VERSION 5.8 ;
BUSBITCHARS "[]" ;
DIVIDERCHAR "/" ;
UNITS
    DATABASE MICRONS 1000 ;
END UNITS

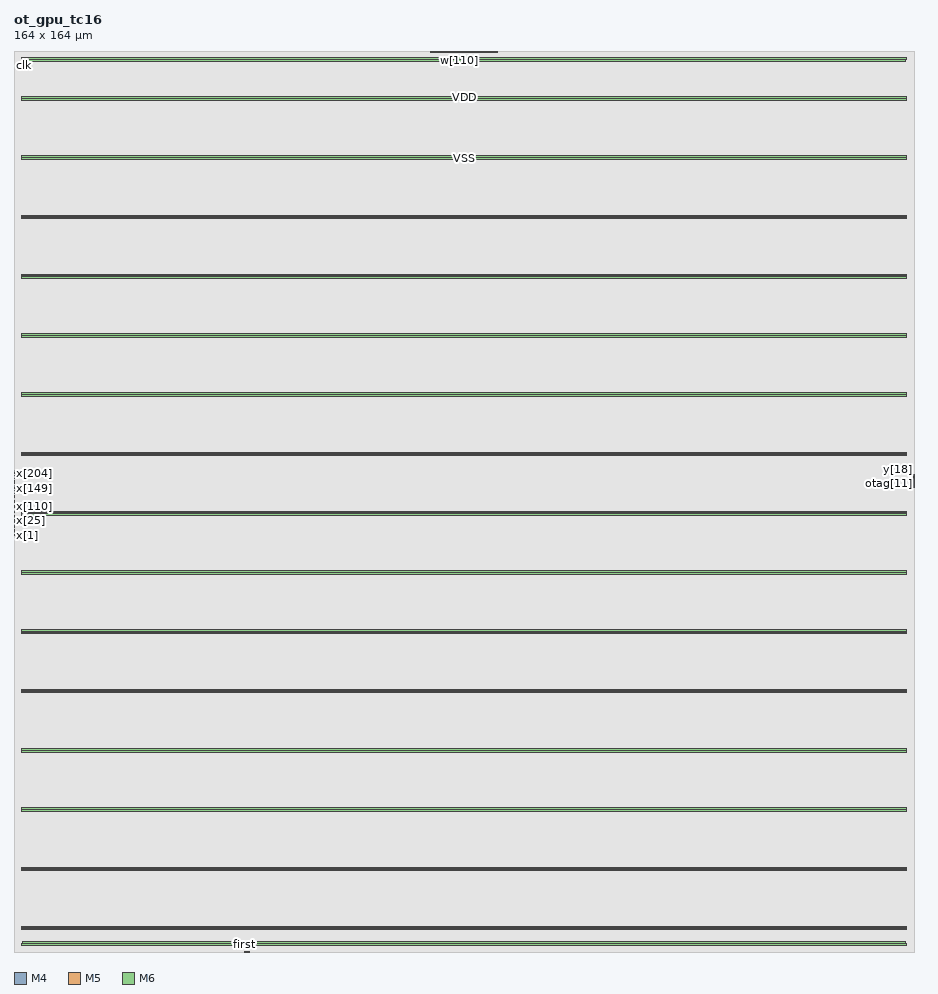
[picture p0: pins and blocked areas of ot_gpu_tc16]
MACRO ot_gpu_tc16
  FOREIGN ot_gpu_tc16 0 0 ;
  CLASS BLOCK ;
  SIZE 164 BY 164 ;
  PIN clk
    DIRECTION INPUT ;
    USE SIGNAL ;
    PORT
      LAYER M4 ;
        RECT  0 161.568 0.084 161.592 ;
    END
  END clk
  PIN fault
    DIRECTION OUTPUT ;
    USE SIGNAL ;
    PORT
      LAYER M4 ;
        RECT  163.916 84.72 164 84.744 ;
    END
  END fault
  PIN first
    DIRECTION INPUT ;
    USE SIGNAL ;
    PORT
      LAYER M5 ;
        RECT  42 0 42.024 0.084 ;
    END
  END first
  PIN last
    DIRECTION INPUT ;
    USE SIGNAL ;
    PORT
      LAYER M5 ;
        RECT  42.048 0 42.072 0.084 ;
    END
  END last
  PIN otag[0]
    DIRECTION OUTPUT ;
    USE SIGNAL ;
    PORT
      LAYER M4 ;
        RECT  163.916 84.768 164 84.792 ;
    END
  END otag[0]
  PIN otag[10]
    DIRECTION OUTPUT ;
    USE SIGNAL ;
    PORT
      LAYER M4 ;
        RECT  163.916 85.248 164 85.272 ;
    END
  END otag[10]
  PIN otag[11]
    DIRECTION OUTPUT ;
    USE SIGNAL ;
    PORT
      LAYER M4 ;
        RECT  163.916 85.296 164 85.32 ;
    END
  END otag[11]
  PIN otag[12]
    DIRECTION OUTPUT ;
    USE SIGNAL ;
    PORT
      LAYER M4 ;
        RECT  163.916 85.344 164 85.368 ;
    END
  END otag[12]
  PIN otag[13]
    DIRECTION OUTPUT ;
    USE SIGNAL ;
    PORT
      LAYER M4 ;
        RECT  163.916 85.392 164 85.416 ;
    END
  END otag[13]
  PIN otag[14]
    DIRECTION OUTPUT ;
    USE SIGNAL ;
    PORT
      LAYER M4 ;
        RECT  163.916 85.44 164 85.464 ;
    END
  END otag[14]
  PIN otag[15]
    DIRECTION OUTPUT ;
    USE SIGNAL ;
    PORT
      LAYER M4 ;
        RECT  163.916 85.488 164 85.512 ;
    END
  END otag[15]
  PIN otag[1]
    DIRECTION OUTPUT ;
    USE SIGNAL ;
    PORT
      LAYER M4 ;
        RECT  163.916 84.816 164 84.84 ;
    END
  END otag[1]
  PIN otag[2]
    DIRECTION OUTPUT ;
    USE SIGNAL ;
    PORT
      LAYER M4 ;
        RECT  163.916 84.864 164 84.888 ;
    END
  END otag[2]
  PIN otag[3]
    DIRECTION OUTPUT ;
    USE SIGNAL ;
    PORT
      LAYER M4 ;
        RECT  163.916 84.912 164 84.936 ;
    END
  END otag[3]
  PIN otag[4]
    DIRECTION OUTPUT ;
    USE SIGNAL ;
    PORT
      LAYER M4 ;
        RECT  163.916 84.96 164 84.984 ;
    END
  END otag[4]
  PIN otag[5]
    DIRECTION OUTPUT ;
    USE SIGNAL ;
    PORT
      LAYER M4 ;
        RECT  163.916 85.008 164 85.032 ;
    END
  END otag[5]
  PIN otag[6]
    DIRECTION OUTPUT ;
    USE SIGNAL ;
    PORT
      LAYER M4 ;
        RECT  163.916 85.056 164 85.08 ;
    END
  END otag[6]
  PIN otag[7]
    DIRECTION OUTPUT ;
    USE SIGNAL ;
    PORT
      LAYER M4 ;
        RECT  163.916 85.104 164 85.128 ;
    END
  END otag[7]
  PIN otag[8]
    DIRECTION OUTPUT ;
    USE SIGNAL ;
    PORT
      LAYER M4 ;
        RECT  163.916 85.152 164 85.176 ;
    END
  END otag[8]
  PIN otag[9]
    DIRECTION OUTPUT ;
    USE SIGNAL ;
    PORT
      LAYER M4 ;
        RECT  163.916 85.2 164 85.224 ;
    END
  END otag[9]
  PIN ov
    DIRECTION OUTPUT ;
    USE SIGNAL ;
    PORT
      LAYER M4 ;
        RECT  163.916 85.536 164 85.56 ;
    END
  END ov
  PIN rst_n
    DIRECTION INPUT ;
    USE SIGNAL ;
    PORT
      LAYER M5 ;
        RECT  42.096 0 42.12 0.084 ;
    END
  END rst_n
  PIN tag[0]
    DIRECTION INPUT ;
    USE SIGNAL ;
    PORT
      LAYER M5 ;
        RECT  42.144 0 42.168 0.084 ;
    END
  END tag[0]
  PIN tag[10]
    DIRECTION INPUT ;
    USE SIGNAL ;
    PORT
      LAYER M5 ;
        RECT  42.624 0 42.648 0.084 ;
    END
  END tag[10]
  PIN tag[11]
    DIRECTION INPUT ;
    USE SIGNAL ;
    PORT
      LAYER M5 ;
        RECT  42.672 0 42.696 0.084 ;
    END
  END tag[11]
  PIN tag[12]
    DIRECTION INPUT ;
    USE SIGNAL ;
    PORT
      LAYER M5 ;
        RECT  42.72 0 42.744 0.084 ;
    END
  END tag[12]
  PIN tag[13]
    DIRECTION INPUT ;
    USE SIGNAL ;
    PORT
      LAYER M5 ;
        RECT  42.768 0 42.792 0.084 ;
    END
  END tag[13]
  PIN tag[14]
    DIRECTION INPUT ;
    USE SIGNAL ;
    PORT
      LAYER M5 ;
        RECT  42.816 0 42.84 0.084 ;
    END
  END tag[14]
  PIN tag[15]
    DIRECTION INPUT ;
    USE SIGNAL ;
    PORT
      LAYER M5 ;
        RECT  42.864 0 42.888 0.084 ;
    END
  END tag[15]
  PIN tag[1]
    DIRECTION INPUT ;
    USE SIGNAL ;
    PORT
      LAYER M5 ;
        RECT  42.192 0 42.216 0.084 ;
    END
  END tag[1]
  PIN tag[2]
    DIRECTION INPUT ;
    USE SIGNAL ;
    PORT
      LAYER M5 ;
        RECT  42.24 0 42.264 0.084 ;
    END
  END tag[2]
  PIN tag[3]
    DIRECTION INPUT ;
    USE SIGNAL ;
    PORT
      LAYER M5 ;
        RECT  42.288 0 42.312 0.084 ;
    END
  END tag[3]
  PIN tag[4]
    DIRECTION INPUT ;
    USE SIGNAL ;
    PORT
      LAYER M5 ;
        RECT  42.336 0 42.36 0.084 ;
    END
  END tag[4]
  PIN tag[5]
    DIRECTION INPUT ;
    USE SIGNAL ;
    PORT
      LAYER M5 ;
        RECT  42.384 0 42.408 0.084 ;
    END
  END tag[5]
  PIN tag[6]
    DIRECTION INPUT ;
    USE SIGNAL ;
    PORT
      LAYER M5 ;
        RECT  42.432 0 42.456 0.084 ;
    END
  END tag[6]
  PIN tag[7]
    DIRECTION INPUT ;
    USE SIGNAL ;
    PORT
      LAYER M5 ;
        RECT  42.48 0 42.504 0.084 ;
    END
  END tag[7]
  PIN tag[8]
    DIRECTION INPUT ;
    USE SIGNAL ;
    PORT
      LAYER M5 ;
        RECT  42.528 0 42.552 0.084 ;
    END
  END tag[8]
  PIN tag[9]
    DIRECTION INPUT ;
    USE SIGNAL ;
    PORT
      LAYER M5 ;
        RECT  42.576 0 42.6 0.084 ;
    END
  END tag[9]
  PIN v
    DIRECTION INPUT ;
    USE SIGNAL ;
    PORT
      LAYER M5 ;
        RECT  42.912 0 42.936 0.084 ;
    END
  END v
  PIN w[0]
    DIRECTION INPUT ;
    USE SIGNAL ;
    PORT
      LAYER M5 ;
        RECT  75.888 163.916 75.912 164 ;
    END
  END w[0]
  PIN w[100]
    DIRECTION INPUT ;
    USE SIGNAL ;
    PORT
      LAYER M5 ;
        RECT  80.688 163.916 80.712 164 ;
    END
  END w[100]
  PIN w[101]
    DIRECTION INPUT ;
    USE SIGNAL ;
    PORT
      LAYER M5 ;
        RECT  80.736 163.916 80.76 164 ;
    END
  END w[101]
  PIN w[102]
    DIRECTION INPUT ;
    USE SIGNAL ;
    PORT
      LAYER M5 ;
        RECT  80.784 163.916 80.808 164 ;
    END
  END w[102]
  PIN w[103]
    DIRECTION INPUT ;
    USE SIGNAL ;
    PORT
      LAYER M5 ;
        RECT  80.832 163.916 80.856 164 ;
    END
  END w[103]
  PIN w[104]
    DIRECTION INPUT ;
    USE SIGNAL ;
    PORT
      LAYER M5 ;
        RECT  80.88 163.916 80.904 164 ;
    END
  END w[104]
  PIN w[105]
    DIRECTION INPUT ;
    USE SIGNAL ;
    PORT
      LAYER M5 ;
        RECT  80.928 163.916 80.952 164 ;
    END
  END w[105]
  PIN w[106]
    DIRECTION INPUT ;
    USE SIGNAL ;
    PORT
      LAYER M5 ;
        RECT  80.976 163.916 81 164 ;
    END
  END w[106]
  PIN w[107]
    DIRECTION INPUT ;
    USE SIGNAL ;
    PORT
      LAYER M5 ;
        RECT  81.024 163.916 81.048 164 ;
    END
  END w[107]
  PIN w[108]
    DIRECTION INPUT ;
    USE SIGNAL ;
    PORT
      LAYER M5 ;
        RECT  81.072 163.916 81.096 164 ;
    END
  END w[108]
  PIN w[109]
    DIRECTION INPUT ;
    USE SIGNAL ;
    PORT
      LAYER M5 ;
        RECT  81.12 163.916 81.144 164 ;
    END
  END w[109]
  PIN w[10]
    DIRECTION INPUT ;
    USE SIGNAL ;
    PORT
      LAYER M5 ;
        RECT  76.368 163.916 76.392 164 ;
    END
  END w[10]
  PIN w[110]
    DIRECTION INPUT ;
    USE SIGNAL ;
    PORT
      LAYER M5 ;
        RECT  81.168 163.916 81.192 164 ;
    END
  END w[110]
  PIN w[111]
    DIRECTION INPUT ;
    USE SIGNAL ;
    PORT
      LAYER M5 ;
        RECT  81.216 163.916 81.24 164 ;
    END
  END w[111]
  PIN w[112]
    DIRECTION INPUT ;
    USE SIGNAL ;
    PORT
      LAYER M5 ;
        RECT  81.264 163.916 81.288 164 ;
    END
  END w[112]
  PIN w[113]
    DIRECTION INPUT ;
    USE SIGNAL ;
    PORT
      LAYER M5 ;
        RECT  81.312 163.916 81.336 164 ;
    END
  END w[113]
  PIN w[114]
    DIRECTION INPUT ;
    USE SIGNAL ;
    PORT
      LAYER M5 ;
        RECT  81.36 163.916 81.384 164 ;
    END
  END w[114]
  PIN w[115]
    DIRECTION INPUT ;
    USE SIGNAL ;
    PORT
      LAYER M5 ;
        RECT  81.408 163.916 81.432 164 ;
    END
  END w[115]
  PIN w[116]
    DIRECTION INPUT ;
    USE SIGNAL ;
    PORT
      LAYER M5 ;
        RECT  81.456 163.916 81.48 164 ;
    END
  END w[116]
  PIN w[117]
    DIRECTION INPUT ;
    USE SIGNAL ;
    PORT
      LAYER M5 ;
        RECT  81.504 163.916 81.528 164 ;
    END
  END w[117]
  PIN w[118]
    DIRECTION INPUT ;
    USE SIGNAL ;
    PORT
      LAYER M5 ;
        RECT  81.552 163.916 81.576 164 ;
    END
  END w[118]
  PIN w[119]
    DIRECTION INPUT ;
    USE SIGNAL ;
    PORT
      LAYER M5 ;
        RECT  81.6 163.916 81.624 164 ;
    END
  END w[119]
  PIN w[11]
    DIRECTION INPUT ;
    USE SIGNAL ;
    PORT
      LAYER M5 ;
        RECT  76.416 163.916 76.44 164 ;
    END
  END w[11]
  PIN w[120]
    DIRECTION INPUT ;
    USE SIGNAL ;
    PORT
      LAYER M5 ;
        RECT  81.648 163.916 81.672 164 ;
    END
  END w[120]
  PIN w[121]
    DIRECTION INPUT ;
    USE SIGNAL ;
    PORT
      LAYER M5 ;
        RECT  81.696 163.916 81.72 164 ;
    END
  END w[121]
  PIN w[122]
    DIRECTION INPUT ;
    USE SIGNAL ;
    PORT
      LAYER M5 ;
        RECT  81.744 163.916 81.768 164 ;
    END
  END w[122]
  PIN w[123]
    DIRECTION INPUT ;
    USE SIGNAL ;
    PORT
      LAYER M5 ;
        RECT  81.792 163.916 81.816 164 ;
    END
  END w[123]
  PIN w[124]
    DIRECTION INPUT ;
    USE SIGNAL ;
    PORT
      LAYER M5 ;
        RECT  81.84 163.916 81.864 164 ;
    END
  END w[124]
  PIN w[125]
    DIRECTION INPUT ;
    USE SIGNAL ;
    PORT
      LAYER M5 ;
        RECT  81.888 163.916 81.912 164 ;
    END
  END w[125]
  PIN w[126]
    DIRECTION INPUT ;
    USE SIGNAL ;
    PORT
      LAYER M5 ;
        RECT  81.936 163.916 81.96 164 ;
    END
  END w[126]
  PIN w[127]
    DIRECTION INPUT ;
    USE SIGNAL ;
    PORT
      LAYER M5 ;
        RECT  81.984 163.916 82.008 164 ;
    END
  END w[127]
  PIN w[128]
    DIRECTION INPUT ;
    USE SIGNAL ;
    PORT
      LAYER M5 ;
        RECT  82.032 163.916 82.056 164 ;
    END
  END w[128]
  PIN w[129]
    DIRECTION INPUT ;
    USE SIGNAL ;
    PORT
      LAYER M5 ;
        RECT  82.08 163.916 82.104 164 ;
    END
  END w[129]
  PIN w[12]
    DIRECTION INPUT ;
    USE SIGNAL ;
    PORT
      LAYER M5 ;
        RECT  76.464 163.916 76.488 164 ;
    END
  END w[12]
  PIN w[130]
    DIRECTION INPUT ;
    USE SIGNAL ;
    PORT
      LAYER M5 ;
        RECT  82.128 163.916 82.152 164 ;
    END
  END w[130]
  PIN w[131]
    DIRECTION INPUT ;
    USE SIGNAL ;
    PORT
      LAYER M5 ;
        RECT  82.176 163.916 82.2 164 ;
    END
  END w[131]
  PIN w[132]
    DIRECTION INPUT ;
    USE SIGNAL ;
    PORT
      LAYER M5 ;
        RECT  82.224 163.916 82.248 164 ;
    END
  END w[132]
  PIN w[133]
    DIRECTION INPUT ;
    USE SIGNAL ;
    PORT
      LAYER M5 ;
        RECT  82.272 163.916 82.296 164 ;
    END
  END w[133]
  PIN w[134]
    DIRECTION INPUT ;
    USE SIGNAL ;
    PORT
      LAYER M5 ;
        RECT  82.32 163.916 82.344 164 ;
    END
  END w[134]
  PIN w[135]
    DIRECTION INPUT ;
    USE SIGNAL ;
    PORT
      LAYER M5 ;
        RECT  82.368 163.916 82.392 164 ;
    END
  END w[135]
  PIN w[136]
    DIRECTION INPUT ;
    USE SIGNAL ;
    PORT
      LAYER M5 ;
        RECT  82.416 163.916 82.44 164 ;
    END
  END w[136]
  PIN w[137]
    DIRECTION INPUT ;
    USE SIGNAL ;
    PORT
      LAYER M5 ;
        RECT  82.464 163.916 82.488 164 ;
    END
  END w[137]
  PIN w[138]
    DIRECTION INPUT ;
    USE SIGNAL ;
    PORT
      LAYER M5 ;
        RECT  82.512 163.916 82.536 164 ;
    END
  END w[138]
  PIN w[139]
    DIRECTION INPUT ;
    USE SIGNAL ;
    PORT
      LAYER M5 ;
        RECT  82.56 163.916 82.584 164 ;
    END
  END w[139]
  PIN w[13]
    DIRECTION INPUT ;
    USE SIGNAL ;
    PORT
      LAYER M5 ;
        RECT  76.512 163.916 76.536 164 ;
    END
  END w[13]
  PIN w[140]
    DIRECTION INPUT ;
    USE SIGNAL ;
    PORT
      LAYER M5 ;
        RECT  82.608 163.916 82.632 164 ;
    END
  END w[140]
  PIN w[141]
    DIRECTION INPUT ;
    USE SIGNAL ;
    PORT
      LAYER M5 ;
        RECT  82.656 163.916 82.68 164 ;
    END
  END w[141]
  PIN w[142]
    DIRECTION INPUT ;
    USE SIGNAL ;
    PORT
      LAYER M5 ;
        RECT  82.704 163.916 82.728 164 ;
    END
  END w[142]
  PIN w[143]
    DIRECTION INPUT ;
    USE SIGNAL ;
    PORT
      LAYER M5 ;
        RECT  82.752 163.916 82.776 164 ;
    END
  END w[143]
  PIN w[144]
    DIRECTION INPUT ;
    USE SIGNAL ;
    PORT
      LAYER M5 ;
        RECT  82.8 163.916 82.824 164 ;
    END
  END w[144]
  PIN w[145]
    DIRECTION INPUT ;
    USE SIGNAL ;
    PORT
      LAYER M5 ;
        RECT  82.848 163.916 82.872 164 ;
    END
  END w[145]
  PIN w[146]
    DIRECTION INPUT ;
    USE SIGNAL ;
    PORT
      LAYER M5 ;
        RECT  82.896 163.916 82.92 164 ;
    END
  END w[146]
  PIN w[147]
    DIRECTION INPUT ;
    USE SIGNAL ;
    PORT
      LAYER M5 ;
        RECT  82.944 163.916 82.968 164 ;
    END
  END w[147]
  PIN w[148]
    DIRECTION INPUT ;
    USE SIGNAL ;
    PORT
      LAYER M5 ;
        RECT  82.992 163.916 83.016 164 ;
    END
  END w[148]
  PIN w[149]
    DIRECTION INPUT ;
    USE SIGNAL ;
    PORT
      LAYER M5 ;
        RECT  83.04 163.916 83.064 164 ;
    END
  END w[149]
  PIN w[14]
    DIRECTION INPUT ;
    USE SIGNAL ;
    PORT
      LAYER M5 ;
        RECT  76.56 163.916 76.584 164 ;
    END
  END w[14]
  PIN w[150]
    DIRECTION INPUT ;
    USE SIGNAL ;
    PORT
      LAYER M5 ;
        RECT  83.088 163.916 83.112 164 ;
    END
  END w[150]
  PIN w[151]
    DIRECTION INPUT ;
    USE SIGNAL ;
    PORT
      LAYER M5 ;
        RECT  83.136 163.916 83.16 164 ;
    END
  END w[151]
  PIN w[152]
    DIRECTION INPUT ;
    USE SIGNAL ;
    PORT
      LAYER M5 ;
        RECT  83.184 163.916 83.208 164 ;
    END
  END w[152]
  PIN w[153]
    DIRECTION INPUT ;
    USE SIGNAL ;
    PORT
      LAYER M5 ;
        RECT  83.232 163.916 83.256 164 ;
    END
  END w[153]
  PIN w[154]
    DIRECTION INPUT ;
    USE SIGNAL ;
    PORT
      LAYER M5 ;
        RECT  83.28 163.916 83.304 164 ;
    END
  END w[154]
  PIN w[155]
    DIRECTION INPUT ;
    USE SIGNAL ;
    PORT
      LAYER M5 ;
        RECT  83.328 163.916 83.352 164 ;
    END
  END w[155]
  PIN w[156]
    DIRECTION INPUT ;
    USE SIGNAL ;
    PORT
      LAYER M5 ;
        RECT  83.376 163.916 83.4 164 ;
    END
  END w[156]
  PIN w[157]
    DIRECTION INPUT ;
    USE SIGNAL ;
    PORT
      LAYER M5 ;
        RECT  83.424 163.916 83.448 164 ;
    END
  END w[157]
  PIN w[158]
    DIRECTION INPUT ;
    USE SIGNAL ;
    PORT
      LAYER M5 ;
        RECT  83.472 163.916 83.496 164 ;
    END
  END w[158]
  PIN w[159]
    DIRECTION INPUT ;
    USE SIGNAL ;
    PORT
      LAYER M5 ;
        RECT  83.52 163.916 83.544 164 ;
    END
  END w[159]
  PIN w[15]
    DIRECTION INPUT ;
    USE SIGNAL ;
    PORT
      LAYER M5 ;
        RECT  76.608 163.916 76.632 164 ;
    END
  END w[15]
  PIN w[160]
    DIRECTION INPUT ;
    USE SIGNAL ;
    PORT
      LAYER M5 ;
        RECT  83.568 163.916 83.592 164 ;
    END
  END w[160]
  PIN w[161]
    DIRECTION INPUT ;
    USE SIGNAL ;
    PORT
      LAYER M5 ;
        RECT  83.616 163.916 83.64 164 ;
    END
  END w[161]
  PIN w[162]
    DIRECTION INPUT ;
    USE SIGNAL ;
    PORT
      LAYER M5 ;
        RECT  83.664 163.916 83.688 164 ;
    END
  END w[162]
  PIN w[163]
    DIRECTION INPUT ;
    USE SIGNAL ;
    PORT
      LAYER M5 ;
        RECT  83.712 163.916 83.736 164 ;
    END
  END w[163]
  PIN w[164]
    DIRECTION INPUT ;
    USE SIGNAL ;
    PORT
      LAYER M5 ;
        RECT  83.76 163.916 83.784 164 ;
    END
  END w[164]
  PIN w[165]
    DIRECTION INPUT ;
    USE SIGNAL ;
    PORT
      LAYER M5 ;
        RECT  83.808 163.916 83.832 164 ;
    END
  END w[165]
  PIN w[166]
    DIRECTION INPUT ;
    USE SIGNAL ;
    PORT
      LAYER M5 ;
        RECT  83.856 163.916 83.88 164 ;
    END
  END w[166]
  PIN w[167]
    DIRECTION INPUT ;
    USE SIGNAL ;
    PORT
      LAYER M5 ;
        RECT  83.904 163.916 83.928 164 ;
    END
  END w[167]
  PIN w[168]
    DIRECTION INPUT ;
    USE SIGNAL ;
    PORT
      LAYER M5 ;
        RECT  83.952 163.916 83.976 164 ;
    END
  END w[168]
  PIN w[169]
    DIRECTION INPUT ;
    USE SIGNAL ;
    PORT
      LAYER M5 ;
        RECT  84 163.916 84.024 164 ;
    END
  END w[169]
  PIN w[16]
    DIRECTION INPUT ;
    USE SIGNAL ;
    PORT
      LAYER M5 ;
        RECT  76.656 163.916 76.68 164 ;
    END
  END w[16]
  PIN w[170]
    DIRECTION INPUT ;
    USE SIGNAL ;
    PORT
      LAYER M5 ;
        RECT  84.048 163.916 84.072 164 ;
    END
  END w[170]
  PIN w[171]
    DIRECTION INPUT ;
    USE SIGNAL ;
    PORT
      LAYER M5 ;
        RECT  84.096 163.916 84.12 164 ;
    END
  END w[171]
  PIN w[172]
    DIRECTION INPUT ;
    USE SIGNAL ;
    PORT
      LAYER M5 ;
        RECT  84.144 163.916 84.168 164 ;
    END
  END w[172]
  PIN w[173]
    DIRECTION INPUT ;
    USE SIGNAL ;
    PORT
      LAYER M5 ;
        RECT  84.192 163.916 84.216 164 ;
    END
  END w[173]
  PIN w[174]
    DIRECTION INPUT ;
    USE SIGNAL ;
    PORT
      LAYER M5 ;
        RECT  84.24 163.916 84.264 164 ;
    END
  END w[174]
  PIN w[175]
    DIRECTION INPUT ;
    USE SIGNAL ;
    PORT
      LAYER M5 ;
        RECT  84.288 163.916 84.312 164 ;
    END
  END w[175]
  PIN w[176]
    DIRECTION INPUT ;
    USE SIGNAL ;
    PORT
      LAYER M5 ;
        RECT  84.336 163.916 84.36 164 ;
    END
  END w[176]
  PIN w[177]
    DIRECTION INPUT ;
    USE SIGNAL ;
    PORT
      LAYER M5 ;
        RECT  84.384 163.916 84.408 164 ;
    END
  END w[177]
  PIN w[178]
    DIRECTION INPUT ;
    USE SIGNAL ;
    PORT
      LAYER M5 ;
        RECT  84.432 163.916 84.456 164 ;
    END
  END w[178]
  PIN w[179]
    DIRECTION INPUT ;
    USE SIGNAL ;
    PORT
      LAYER M5 ;
        RECT  84.48 163.916 84.504 164 ;
    END
  END w[179]
  PIN w[17]
    DIRECTION INPUT ;
    USE SIGNAL ;
    PORT
      LAYER M5 ;
        RECT  76.704 163.916 76.728 164 ;
    END
  END w[17]
  PIN w[180]
    DIRECTION INPUT ;
    USE SIGNAL ;
    PORT
      LAYER M5 ;
        RECT  84.528 163.916 84.552 164 ;
    END
  END w[180]
  PIN w[181]
    DIRECTION INPUT ;
    USE SIGNAL ;
    PORT
      LAYER M5 ;
        RECT  84.576 163.916 84.6 164 ;
    END
  END w[181]
  PIN w[182]
    DIRECTION INPUT ;
    USE SIGNAL ;
    PORT
      LAYER M5 ;
        RECT  84.624 163.916 84.648 164 ;
    END
  END w[182]
  PIN w[183]
    DIRECTION INPUT ;
    USE SIGNAL ;
    PORT
      LAYER M5 ;
        RECT  84.672 163.916 84.696 164 ;
    END
  END w[183]
  PIN w[184]
    DIRECTION INPUT ;
    USE SIGNAL ;
    PORT
      LAYER M5 ;
        RECT  84.72 163.916 84.744 164 ;
    END
  END w[184]
  PIN w[185]
    DIRECTION INPUT ;
    USE SIGNAL ;
    PORT
      LAYER M5 ;
        RECT  84.768 163.916 84.792 164 ;
    END
  END w[185]
  PIN w[186]
    DIRECTION INPUT ;
    USE SIGNAL ;
    PORT
      LAYER M5 ;
        RECT  84.816 163.916 84.84 164 ;
    END
  END w[186]
  PIN w[187]
    DIRECTION INPUT ;
    USE SIGNAL ;
    PORT
      LAYER M5 ;
        RECT  84.864 163.916 84.888 164 ;
    END
  END w[187]
  PIN w[188]
    DIRECTION INPUT ;
    USE SIGNAL ;
    PORT
      LAYER M5 ;
        RECT  84.912 163.916 84.936 164 ;
    END
  END w[188]
  PIN w[189]
    DIRECTION INPUT ;
    USE SIGNAL ;
    PORT
      LAYER M5 ;
        RECT  84.96 163.916 84.984 164 ;
    END
  END w[189]
  PIN w[18]
    DIRECTION INPUT ;
    USE SIGNAL ;
    PORT
      LAYER M5 ;
        RECT  76.752 163.916 76.776 164 ;
    END
  END w[18]
  PIN w[190]
    DIRECTION INPUT ;
    USE SIGNAL ;
    PORT
      LAYER M5 ;
        RECT  85.008 163.916 85.032 164 ;
    END
  END w[190]
  PIN w[191]
    DIRECTION INPUT ;
    USE SIGNAL ;
    PORT
      LAYER M5 ;
        RECT  85.056 163.916 85.08 164 ;
    END
  END w[191]
  PIN w[192]
    DIRECTION INPUT ;
    USE SIGNAL ;
    PORT
      LAYER M5 ;
        RECT  85.104 163.916 85.128 164 ;
    END
  END w[192]
  PIN w[193]
    DIRECTION INPUT ;
    USE SIGNAL ;
    PORT
      LAYER M5 ;
        RECT  85.152 163.916 85.176 164 ;
    END
  END w[193]
  PIN w[194]
    DIRECTION INPUT ;
    USE SIGNAL ;
    PORT
      LAYER M5 ;
        RECT  85.2 163.916 85.224 164 ;
    END
  END w[194]
  PIN w[195]
    DIRECTION INPUT ;
    USE SIGNAL ;
    PORT
      LAYER M5 ;
        RECT  85.248 163.916 85.272 164 ;
    END
  END w[195]
  PIN w[196]
    DIRECTION INPUT ;
    USE SIGNAL ;
    PORT
      LAYER M5 ;
        RECT  85.296 163.916 85.32 164 ;
    END
  END w[196]
  PIN w[197]
    DIRECTION INPUT ;
    USE SIGNAL ;
    PORT
      LAYER M5 ;
        RECT  85.344 163.916 85.368 164 ;
    END
  END w[197]
  PIN w[198]
    DIRECTION INPUT ;
    USE SIGNAL ;
    PORT
      LAYER M5 ;
        RECT  85.392 163.916 85.416 164 ;
    END
  END w[198]
  PIN w[199]
    DIRECTION INPUT ;
    USE SIGNAL ;
    PORT
      LAYER M5 ;
        RECT  85.44 163.916 85.464 164 ;
    END
  END w[199]
  PIN w[19]
    DIRECTION INPUT ;
    USE SIGNAL ;
    PORT
      LAYER M5 ;
        RECT  76.8 163.916 76.824 164 ;
    END
  END w[19]
  PIN w[1]
    DIRECTION INPUT ;
    USE SIGNAL ;
    PORT
      LAYER M5 ;
        RECT  75.936 163.916 75.96 164 ;
    END
  END w[1]
  PIN w[200]
    DIRECTION INPUT ;
    USE SIGNAL ;
    PORT
      LAYER M5 ;
        RECT  85.488 163.916 85.512 164 ;
    END
  END w[200]
  PIN w[201]
    DIRECTION INPUT ;
    USE SIGNAL ;
    PORT
      LAYER M5 ;
        RECT  85.536 163.916 85.56 164 ;
    END
  END w[201]
  PIN w[202]
    DIRECTION INPUT ;
    USE SIGNAL ;
    PORT
      LAYER M5 ;
        RECT  85.584 163.916 85.608 164 ;
    END
  END w[202]
  PIN w[203]
    DIRECTION INPUT ;
    USE SIGNAL ;
    PORT
      LAYER M5 ;
        RECT  85.632 163.916 85.656 164 ;
    END
  END w[203]
  PIN w[204]
    DIRECTION INPUT ;
    USE SIGNAL ;
    PORT
      LAYER M5 ;
        RECT  85.68 163.916 85.704 164 ;
    END
  END w[204]
  PIN w[205]
    DIRECTION INPUT ;
    USE SIGNAL ;
    PORT
      LAYER M5 ;
        RECT  85.728 163.916 85.752 164 ;
    END
  END w[205]
  PIN w[206]
    DIRECTION INPUT ;
    USE SIGNAL ;
    PORT
      LAYER M5 ;
        RECT  85.776 163.916 85.8 164 ;
    END
  END w[206]
  PIN w[207]
    DIRECTION INPUT ;
    USE SIGNAL ;
    PORT
      LAYER M5 ;
        RECT  85.824 163.916 85.848 164 ;
    END
  END w[207]
  PIN w[208]
    DIRECTION INPUT ;
    USE SIGNAL ;
    PORT
      LAYER M5 ;
        RECT  85.872 163.916 85.896 164 ;
    END
  END w[208]
  PIN w[209]
    DIRECTION INPUT ;
    USE SIGNAL ;
    PORT
      LAYER M5 ;
        RECT  85.92 163.916 85.944 164 ;
    END
  END w[209]
  PIN w[20]
    DIRECTION INPUT ;
    USE SIGNAL ;
    PORT
      LAYER M5 ;
        RECT  76.848 163.916 76.872 164 ;
    END
  END w[20]
  PIN w[210]
    DIRECTION INPUT ;
    USE SIGNAL ;
    PORT
      LAYER M5 ;
        RECT  85.968 163.916 85.992 164 ;
    END
  END w[210]
  PIN w[211]
    DIRECTION INPUT ;
    USE SIGNAL ;
    PORT
      LAYER M5 ;
        RECT  86.016 163.916 86.04 164 ;
    END
  END w[211]
  PIN w[212]
    DIRECTION INPUT ;
    USE SIGNAL ;
    PORT
      LAYER M5 ;
        RECT  86.064 163.916 86.088 164 ;
    END
  END w[212]
  PIN w[213]
    DIRECTION INPUT ;
    USE SIGNAL ;
    PORT
      LAYER M5 ;
        RECT  86.112 163.916 86.136 164 ;
    END
  END w[213]
  PIN w[214]
    DIRECTION INPUT ;
    USE SIGNAL ;
    PORT
      LAYER M5 ;
        RECT  86.16 163.916 86.184 164 ;
    END
  END w[214]
  PIN w[215]
    DIRECTION INPUT ;
    USE SIGNAL ;
    PORT
      LAYER M5 ;
        RECT  86.208 163.916 86.232 164 ;
    END
  END w[215]
  PIN w[216]
    DIRECTION INPUT ;
    USE SIGNAL ;
    PORT
      LAYER M5 ;
        RECT  86.256 163.916 86.28 164 ;
    END
  END w[216]
  PIN w[217]
    DIRECTION INPUT ;
    USE SIGNAL ;
    PORT
      LAYER M5 ;
        RECT  86.304 163.916 86.328 164 ;
    END
  END w[217]
  PIN w[218]
    DIRECTION INPUT ;
    USE SIGNAL ;
    PORT
      LAYER M5 ;
        RECT  86.352 163.916 86.376 164 ;
    END
  END w[218]
  PIN w[219]
    DIRECTION INPUT ;
    USE SIGNAL ;
    PORT
      LAYER M5 ;
        RECT  86.4 163.916 86.424 164 ;
    END
  END w[219]
  PIN w[21]
    DIRECTION INPUT ;
    USE SIGNAL ;
    PORT
      LAYER M5 ;
        RECT  76.896 163.916 76.92 164 ;
    END
  END w[21]
  PIN w[220]
    DIRECTION INPUT ;
    USE SIGNAL ;
    PORT
      LAYER M5 ;
        RECT  86.448 163.916 86.472 164 ;
    END
  END w[220]
  PIN w[221]
    DIRECTION INPUT ;
    USE SIGNAL ;
    PORT
      LAYER M5 ;
        RECT  86.496 163.916 86.52 164 ;
    END
  END w[221]
  PIN w[222]
    DIRECTION INPUT ;
    USE SIGNAL ;
    PORT
      LAYER M5 ;
        RECT  86.544 163.916 86.568 164 ;
    END
  END w[222]
  PIN w[223]
    DIRECTION INPUT ;
    USE SIGNAL ;
    PORT
      LAYER M5 ;
        RECT  86.592 163.916 86.616 164 ;
    END
  END w[223]
  PIN w[224]
    DIRECTION INPUT ;
    USE SIGNAL ;
    PORT
      LAYER M5 ;
        RECT  86.64 163.916 86.664 164 ;
    END
  END w[224]
  PIN w[225]
    DIRECTION INPUT ;
    USE SIGNAL ;
    PORT
      LAYER M5 ;
        RECT  86.688 163.916 86.712 164 ;
    END
  END w[225]
  PIN w[226]
    DIRECTION INPUT ;
    USE SIGNAL ;
    PORT
      LAYER M5 ;
        RECT  86.736 163.916 86.76 164 ;
    END
  END w[226]
  PIN w[227]
    DIRECTION INPUT ;
    USE SIGNAL ;
    PORT
      LAYER M5 ;
        RECT  86.784 163.916 86.808 164 ;
    END
  END w[227]
  PIN w[228]
    DIRECTION INPUT ;
    USE SIGNAL ;
    PORT
      LAYER M5 ;
        RECT  86.832 163.916 86.856 164 ;
    END
  END w[228]
  PIN w[229]
    DIRECTION INPUT ;
    USE SIGNAL ;
    PORT
      LAYER M5 ;
        RECT  86.88 163.916 86.904 164 ;
    END
  END w[229]
  PIN w[22]
    DIRECTION INPUT ;
    USE SIGNAL ;
    PORT
      LAYER M5 ;
        RECT  76.944 163.916 76.968 164 ;
    END
  END w[22]
  PIN w[230]
    DIRECTION INPUT ;
    USE SIGNAL ;
    PORT
      LAYER M5 ;
        RECT  86.928 163.916 86.952 164 ;
    END
  END w[230]
  PIN w[231]
    DIRECTION INPUT ;
    USE SIGNAL ;
    PORT
      LAYER M5 ;
        RECT  86.976 163.916 87 164 ;
    END
  END w[231]
  PIN w[232]
    DIRECTION INPUT ;
    USE SIGNAL ;
    PORT
      LAYER M5 ;
        RECT  87.024 163.916 87.048 164 ;
    END
  END w[232]
  PIN w[233]
    DIRECTION INPUT ;
    USE SIGNAL ;
    PORT
      LAYER M5 ;
        RECT  87.072 163.916 87.096 164 ;
    END
  END w[233]
  PIN w[234]
    DIRECTION INPUT ;
    USE SIGNAL ;
    PORT
      LAYER M5 ;
        RECT  87.12 163.916 87.144 164 ;
    END
  END w[234]
  PIN w[235]
    DIRECTION INPUT ;
    USE SIGNAL ;
    PORT
      LAYER M5 ;
        RECT  87.168 163.916 87.192 164 ;
    END
  END w[235]
  PIN w[236]
    DIRECTION INPUT ;
    USE SIGNAL ;
    PORT
      LAYER M5 ;
        RECT  87.216 163.916 87.24 164 ;
    END
  END w[236]
  PIN w[237]
    DIRECTION INPUT ;
    USE SIGNAL ;
    PORT
      LAYER M5 ;
        RECT  87.264 163.916 87.288 164 ;
    END
  END w[237]
  PIN w[238]
    DIRECTION INPUT ;
    USE SIGNAL ;
    PORT
      LAYER M5 ;
        RECT  87.312 163.916 87.336 164 ;
    END
  END w[238]
  PIN w[239]
    DIRECTION INPUT ;
    USE SIGNAL ;
    PORT
      LAYER M5 ;
        RECT  87.36 163.916 87.384 164 ;
    END
  END w[239]
  PIN w[23]
    DIRECTION INPUT ;
    USE SIGNAL ;
    PORT
      LAYER M5 ;
        RECT  76.992 163.916 77.016 164 ;
    END
  END w[23]
  PIN w[240]
    DIRECTION INPUT ;
    USE SIGNAL ;
    PORT
      LAYER M5 ;
        RECT  87.408 163.916 87.432 164 ;
    END
  END w[240]
  PIN w[241]
    DIRECTION INPUT ;
    USE SIGNAL ;
    PORT
      LAYER M5 ;
        RECT  87.456 163.916 87.48 164 ;
    END
  END w[241]
  PIN w[242]
    DIRECTION INPUT ;
    USE SIGNAL ;
    PORT
      LAYER M5 ;
        RECT  87.504 163.916 87.528 164 ;
    END
  END w[242]
  PIN w[243]
    DIRECTION INPUT ;
    USE SIGNAL ;
    PORT
      LAYER M5 ;
        RECT  87.552 163.916 87.576 164 ;
    END
  END w[243]
  PIN w[244]
    DIRECTION INPUT ;
    USE SIGNAL ;
    PORT
      LAYER M5 ;
        RECT  87.6 163.916 87.624 164 ;
    END
  END w[244]
  PIN w[245]
    DIRECTION INPUT ;
    USE SIGNAL ;
    PORT
      LAYER M5 ;
        RECT  87.648 163.916 87.672 164 ;
    END
  END w[245]
  PIN w[246]
    DIRECTION INPUT ;
    USE SIGNAL ;
    PORT
      LAYER M5 ;
        RECT  87.696 163.916 87.72 164 ;
    END
  END w[246]
  PIN w[247]
    DIRECTION INPUT ;
    USE SIGNAL ;
    PORT
      LAYER M5 ;
        RECT  87.744 163.916 87.768 164 ;
    END
  END w[247]
  PIN w[248]
    DIRECTION INPUT ;
    USE SIGNAL ;
    PORT
      LAYER M5 ;
        RECT  87.792 163.916 87.816 164 ;
    END
  END w[248]
  PIN w[249]
    DIRECTION INPUT ;
    USE SIGNAL ;
    PORT
      LAYER M5 ;
        RECT  87.84 163.916 87.864 164 ;
    END
  END w[249]
  PIN w[24]
    DIRECTION INPUT ;
    USE SIGNAL ;
    PORT
      LAYER M5 ;
        RECT  77.04 163.916 77.064 164 ;
    END
  END w[24]
  PIN w[250]
    DIRECTION INPUT ;
    USE SIGNAL ;
    PORT
      LAYER M5 ;
        RECT  87.888 163.916 87.912 164 ;
    END
  END w[250]
  PIN w[251]
    DIRECTION INPUT ;
    USE SIGNAL ;
    PORT
      LAYER M5 ;
        RECT  87.936 163.916 87.96 164 ;
    END
  END w[251]
  PIN w[252]
    DIRECTION INPUT ;
    USE SIGNAL ;
    PORT
      LAYER M5 ;
        RECT  87.984 163.916 88.008 164 ;
    END
  END w[252]
  PIN w[253]
    DIRECTION INPUT ;
    USE SIGNAL ;
    PORT
      LAYER M5 ;
        RECT  88.032 163.916 88.056 164 ;
    END
  END w[253]
  PIN w[254]
    DIRECTION INPUT ;
    USE SIGNAL ;
    PORT
      LAYER M5 ;
        RECT  88.08 163.916 88.104 164 ;
    END
  END w[254]
  PIN w[255]
    DIRECTION INPUT ;
    USE SIGNAL ;
    PORT
      LAYER M5 ;
        RECT  88.128 163.916 88.152 164 ;
    END
  END w[255]
  PIN w[25]
    DIRECTION INPUT ;
    USE SIGNAL ;
    PORT
      LAYER M5 ;
        RECT  77.088 163.916 77.112 164 ;
    END
  END w[25]
  PIN w[26]
    DIRECTION INPUT ;
    USE SIGNAL ;
    PORT
      LAYER M5 ;
        RECT  77.136 163.916 77.16 164 ;
    END
  END w[26]
  PIN w[27]
    DIRECTION INPUT ;
    USE SIGNAL ;
    PORT
      LAYER M5 ;
        RECT  77.184 163.916 77.208 164 ;
    END
  END w[27]
  PIN w[28]
    DIRECTION INPUT ;
    USE SIGNAL ;
    PORT
      LAYER M5 ;
        RECT  77.232 163.916 77.256 164 ;
    END
  END w[28]
  PIN w[29]
    DIRECTION INPUT ;
    USE SIGNAL ;
    PORT
      LAYER M5 ;
        RECT  77.28 163.916 77.304 164 ;
    END
  END w[29]
  PIN w[2]
    DIRECTION INPUT ;
    USE SIGNAL ;
    PORT
      LAYER M5 ;
        RECT  75.984 163.916 76.008 164 ;
    END
  END w[2]
  PIN w[30]
    DIRECTION INPUT ;
    USE SIGNAL ;
    PORT
      LAYER M5 ;
        RECT  77.328 163.916 77.352 164 ;
    END
  END w[30]
  PIN w[31]
    DIRECTION INPUT ;
    USE SIGNAL ;
    PORT
      LAYER M5 ;
        RECT  77.376 163.916 77.4 164 ;
    END
  END w[31]
  PIN w[32]
    DIRECTION INPUT ;
    USE SIGNAL ;
    PORT
      LAYER M5 ;
        RECT  77.424 163.916 77.448 164 ;
    END
  END w[32]
  PIN w[33]
    DIRECTION INPUT ;
    USE SIGNAL ;
    PORT
      LAYER M5 ;
        RECT  77.472 163.916 77.496 164 ;
    END
  END w[33]
  PIN w[34]
    DIRECTION INPUT ;
    USE SIGNAL ;
    PORT
      LAYER M5 ;
        RECT  77.52 163.916 77.544 164 ;
    END
  END w[34]
  PIN w[35]
    DIRECTION INPUT ;
    USE SIGNAL ;
    PORT
      LAYER M5 ;
        RECT  77.568 163.916 77.592 164 ;
    END
  END w[35]
  PIN w[36]
    DIRECTION INPUT ;
    USE SIGNAL ;
    PORT
      LAYER M5 ;
        RECT  77.616 163.916 77.64 164 ;
    END
  END w[36]
  PIN w[37]
    DIRECTION INPUT ;
    USE SIGNAL ;
    PORT
      LAYER M5 ;
        RECT  77.664 163.916 77.688 164 ;
    END
  END w[37]
  PIN w[38]
    DIRECTION INPUT ;
    USE SIGNAL ;
    PORT
      LAYER M5 ;
        RECT  77.712 163.916 77.736 164 ;
    END
  END w[38]
  PIN w[39]
    DIRECTION INPUT ;
    USE SIGNAL ;
    PORT
      LAYER M5 ;
        RECT  77.76 163.916 77.784 164 ;
    END
  END w[39]
  PIN w[3]
    DIRECTION INPUT ;
    USE SIGNAL ;
    PORT
      LAYER M5 ;
        RECT  76.032 163.916 76.056 164 ;
    END
  END w[3]
  PIN w[40]
    DIRECTION INPUT ;
    USE SIGNAL ;
    PORT
      LAYER M5 ;
        RECT  77.808 163.916 77.832 164 ;
    END
  END w[40]
  PIN w[41]
    DIRECTION INPUT ;
    USE SIGNAL ;
    PORT
      LAYER M5 ;
        RECT  77.856 163.916 77.88 164 ;
    END
  END w[41]
  PIN w[42]
    DIRECTION INPUT ;
    USE SIGNAL ;
    PORT
      LAYER M5 ;
        RECT  77.904 163.916 77.928 164 ;
    END
  END w[42]
  PIN w[43]
    DIRECTION INPUT ;
    USE SIGNAL ;
    PORT
      LAYER M5 ;
        RECT  77.952 163.916 77.976 164 ;
    END
  END w[43]
  PIN w[44]
    DIRECTION INPUT ;
    USE SIGNAL ;
    PORT
      LAYER M5 ;
        RECT  78 163.916 78.024 164 ;
    END
  END w[44]
  PIN w[45]
    DIRECTION INPUT ;
    USE SIGNAL ;
    PORT
      LAYER M5 ;
        RECT  78.048 163.916 78.072 164 ;
    END
  END w[45]
  PIN w[46]
    DIRECTION INPUT ;
    USE SIGNAL ;
    PORT
      LAYER M5 ;
        RECT  78.096 163.916 78.12 164 ;
    END
  END w[46]
  PIN w[47]
    DIRECTION INPUT ;
    USE SIGNAL ;
    PORT
      LAYER M5 ;
        RECT  78.144 163.916 78.168 164 ;
    END
  END w[47]
  PIN w[48]
    DIRECTION INPUT ;
    USE SIGNAL ;
    PORT
      LAYER M5 ;
        RECT  78.192 163.916 78.216 164 ;
    END
  END w[48]
  PIN w[49]
    DIRECTION INPUT ;
    USE SIGNAL ;
    PORT
      LAYER M5 ;
        RECT  78.24 163.916 78.264 164 ;
    END
  END w[49]
  PIN w[4]
    DIRECTION INPUT ;
    USE SIGNAL ;
    PORT
      LAYER M5 ;
        RECT  76.08 163.916 76.104 164 ;
    END
  END w[4]
  PIN w[50]
    DIRECTION INPUT ;
    USE SIGNAL ;
    PORT
      LAYER M5 ;
        RECT  78.288 163.916 78.312 164 ;
    END
  END w[50]
  PIN w[51]
    DIRECTION INPUT ;
    USE SIGNAL ;
    PORT
      LAYER M5 ;
        RECT  78.336 163.916 78.36 164 ;
    END
  END w[51]
  PIN w[52]
    DIRECTION INPUT ;
    USE SIGNAL ;
    PORT
      LAYER M5 ;
        RECT  78.384 163.916 78.408 164 ;
    END
  END w[52]
  PIN w[53]
    DIRECTION INPUT ;
    USE SIGNAL ;
    PORT
      LAYER M5 ;
        RECT  78.432 163.916 78.456 164 ;
    END
  END w[53]
  PIN w[54]
    DIRECTION INPUT ;
    USE SIGNAL ;
    PORT
      LAYER M5 ;
        RECT  78.48 163.916 78.504 164 ;
    END
  END w[54]
  PIN w[55]
    DIRECTION INPUT ;
    USE SIGNAL ;
    PORT
      LAYER M5 ;
        RECT  78.528 163.916 78.552 164 ;
    END
  END w[55]
  PIN w[56]
    DIRECTION INPUT ;
    USE SIGNAL ;
    PORT
      LAYER M5 ;
        RECT  78.576 163.916 78.6 164 ;
    END
  END w[56]
  PIN w[57]
    DIRECTION INPUT ;
    USE SIGNAL ;
    PORT
      LAYER M5 ;
        RECT  78.624 163.916 78.648 164 ;
    END
  END w[57]
  PIN w[58]
    DIRECTION INPUT ;
    USE SIGNAL ;
    PORT
      LAYER M5 ;
        RECT  78.672 163.916 78.696 164 ;
    END
  END w[58]
  PIN w[59]
    DIRECTION INPUT ;
    USE SIGNAL ;
    PORT
      LAYER M5 ;
        RECT  78.72 163.916 78.744 164 ;
    END
  END w[59]
  PIN w[5]
    DIRECTION INPUT ;
    USE SIGNAL ;
    PORT
      LAYER M5 ;
        RECT  76.128 163.916 76.152 164 ;
    END
  END w[5]
  PIN w[60]
    DIRECTION INPUT ;
    USE SIGNAL ;
    PORT
      LAYER M5 ;
        RECT  78.768 163.916 78.792 164 ;
    END
  END w[60]
  PIN w[61]
    DIRECTION INPUT ;
    USE SIGNAL ;
    PORT
      LAYER M5 ;
        RECT  78.816 163.916 78.84 164 ;
    END
  END w[61]
  PIN w[62]
    DIRECTION INPUT ;
    USE SIGNAL ;
    PORT
      LAYER M5 ;
        RECT  78.864 163.916 78.888 164 ;
    END
  END w[62]
  PIN w[63]
    DIRECTION INPUT ;
    USE SIGNAL ;
    PORT
      LAYER M5 ;
        RECT  78.912 163.916 78.936 164 ;
    END
  END w[63]
  PIN w[64]
    DIRECTION INPUT ;
    USE SIGNAL ;
    PORT
      LAYER M5 ;
        RECT  78.96 163.916 78.984 164 ;
    END
  END w[64]
  PIN w[65]
    DIRECTION INPUT ;
    USE SIGNAL ;
    PORT
      LAYER M5 ;
        RECT  79.008 163.916 79.032 164 ;
    END
  END w[65]
  PIN w[66]
    DIRECTION INPUT ;
    USE SIGNAL ;
    PORT
      LAYER M5 ;
        RECT  79.056 163.916 79.08 164 ;
    END
  END w[66]
  PIN w[67]
    DIRECTION INPUT ;
    USE SIGNAL ;
    PORT
      LAYER M5 ;
        RECT  79.104 163.916 79.128 164 ;
    END
  END w[67]
  PIN w[68]
    DIRECTION INPUT ;
    USE SIGNAL ;
    PORT
      LAYER M5 ;
        RECT  79.152 163.916 79.176 164 ;
    END
  END w[68]
  PIN w[69]
    DIRECTION INPUT ;
    USE SIGNAL ;
    PORT
      LAYER M5 ;
        RECT  79.2 163.916 79.224 164 ;
    END
  END w[69]
  PIN w[6]
    DIRECTION INPUT ;
    USE SIGNAL ;
    PORT
      LAYER M5 ;
        RECT  76.176 163.916 76.2 164 ;
    END
  END w[6]
  PIN w[70]
    DIRECTION INPUT ;
    USE SIGNAL ;
    PORT
      LAYER M5 ;
        RECT  79.248 163.916 79.272 164 ;
    END
  END w[70]
  PIN w[71]
    DIRECTION INPUT ;
    USE SIGNAL ;
    PORT
      LAYER M5 ;
        RECT  79.296 163.916 79.32 164 ;
    END
  END w[71]
  PIN w[72]
    DIRECTION INPUT ;
    USE SIGNAL ;
    PORT
      LAYER M5 ;
        RECT  79.344 163.916 79.368 164 ;
    END
  END w[72]
  PIN w[73]
    DIRECTION INPUT ;
    USE SIGNAL ;
    PORT
      LAYER M5 ;
        RECT  79.392 163.916 79.416 164 ;
    END
  END w[73]
  PIN w[74]
    DIRECTION INPUT ;
    USE SIGNAL ;
    PORT
      LAYER M5 ;
        RECT  79.44 163.916 79.464 164 ;
    END
  END w[74]
  PIN w[75]
    DIRECTION INPUT ;
    USE SIGNAL ;
    PORT
      LAYER M5 ;
        RECT  79.488 163.916 79.512 164 ;
    END
  END w[75]
  PIN w[76]
    DIRECTION INPUT ;
    USE SIGNAL ;
    PORT
      LAYER M5 ;
        RECT  79.536 163.916 79.56 164 ;
    END
  END w[76]
  PIN w[77]
    DIRECTION INPUT ;
    USE SIGNAL ;
    PORT
      LAYER M5 ;
        RECT  79.584 163.916 79.608 164 ;
    END
  END w[77]
  PIN w[78]
    DIRECTION INPUT ;
    USE SIGNAL ;
    PORT
      LAYER M5 ;
        RECT  79.632 163.916 79.656 164 ;
    END
  END w[78]
  PIN w[79]
    DIRECTION INPUT ;
    USE SIGNAL ;
    PORT
      LAYER M5 ;
        RECT  79.68 163.916 79.704 164 ;
    END
  END w[79]
  PIN w[7]
    DIRECTION INPUT ;
    USE SIGNAL ;
    PORT
      LAYER M5 ;
        RECT  76.224 163.916 76.248 164 ;
    END
  END w[7]
  PIN w[80]
    DIRECTION INPUT ;
    USE SIGNAL ;
    PORT
      LAYER M5 ;
        RECT  79.728 163.916 79.752 164 ;
    END
  END w[80]
  PIN w[81]
    DIRECTION INPUT ;
    USE SIGNAL ;
    PORT
      LAYER M5 ;
        RECT  79.776 163.916 79.8 164 ;
    END
  END w[81]
  PIN w[82]
    DIRECTION INPUT ;
    USE SIGNAL ;
    PORT
      LAYER M5 ;
        RECT  79.824 163.916 79.848 164 ;
    END
  END w[82]
  PIN w[83]
    DIRECTION INPUT ;
    USE SIGNAL ;
    PORT
      LAYER M5 ;
        RECT  79.872 163.916 79.896 164 ;
    END
  END w[83]
  PIN w[84]
    DIRECTION INPUT ;
    USE SIGNAL ;
    PORT
      LAYER M5 ;
        RECT  79.92 163.916 79.944 164 ;
    END
  END w[84]
  PIN w[85]
    DIRECTION INPUT ;
    USE SIGNAL ;
    PORT
      LAYER M5 ;
        RECT  79.968 163.916 79.992 164 ;
    END
  END w[85]
  PIN w[86]
    DIRECTION INPUT ;
    USE SIGNAL ;
    PORT
      LAYER M5 ;
        RECT  80.016 163.916 80.04 164 ;
    END
  END w[86]
  PIN w[87]
    DIRECTION INPUT ;
    USE SIGNAL ;
    PORT
      LAYER M5 ;
        RECT  80.064 163.916 80.088 164 ;
    END
  END w[87]
  PIN w[88]
    DIRECTION INPUT ;
    USE SIGNAL ;
    PORT
      LAYER M5 ;
        RECT  80.112 163.916 80.136 164 ;
    END
  END w[88]
  PIN w[89]
    DIRECTION INPUT ;
    USE SIGNAL ;
    PORT
      LAYER M5 ;
        RECT  80.16 163.916 80.184 164 ;
    END
  END w[89]
  PIN w[8]
    DIRECTION INPUT ;
    USE SIGNAL ;
    PORT
      LAYER M5 ;
        RECT  76.272 163.916 76.296 164 ;
    END
  END w[8]
  PIN w[90]
    DIRECTION INPUT ;
    USE SIGNAL ;
    PORT
      LAYER M5 ;
        RECT  80.208 163.916 80.232 164 ;
    END
  END w[90]
  PIN w[91]
    DIRECTION INPUT ;
    USE SIGNAL ;
    PORT
      LAYER M5 ;
        RECT  80.256 163.916 80.28 164 ;
    END
  END w[91]
  PIN w[92]
    DIRECTION INPUT ;
    USE SIGNAL ;
    PORT
      LAYER M5 ;
        RECT  80.304 163.916 80.328 164 ;
    END
  END w[92]
  PIN w[93]
    DIRECTION INPUT ;
    USE SIGNAL ;
    PORT
      LAYER M5 ;
        RECT  80.352 163.916 80.376 164 ;
    END
  END w[93]
  PIN w[94]
    DIRECTION INPUT ;
    USE SIGNAL ;
    PORT
      LAYER M5 ;
        RECT  80.4 163.916 80.424 164 ;
    END
  END w[94]
  PIN w[95]
    DIRECTION INPUT ;
    USE SIGNAL ;
    PORT
      LAYER M5 ;
        RECT  80.448 163.916 80.472 164 ;
    END
  END w[95]
  PIN w[96]
    DIRECTION INPUT ;
    USE SIGNAL ;
    PORT
      LAYER M5 ;
        RECT  80.496 163.916 80.52 164 ;
    END
  END w[96]
  PIN w[97]
    DIRECTION INPUT ;
    USE SIGNAL ;
    PORT
      LAYER M5 ;
        RECT  80.544 163.916 80.568 164 ;
    END
  END w[97]
  PIN w[98]
    DIRECTION INPUT ;
    USE SIGNAL ;
    PORT
      LAYER M5 ;
        RECT  80.592 163.916 80.616 164 ;
    END
  END w[98]
  PIN w[99]
    DIRECTION INPUT ;
    USE SIGNAL ;
    PORT
      LAYER M5 ;
        RECT  80.64 163.916 80.664 164 ;
    END
  END w[99]
  PIN w[9]
    DIRECTION INPUT ;
    USE SIGNAL ;
    PORT
      LAYER M5 ;
        RECT  76.32 163.916 76.344 164 ;
    END
  END w[9]
  PIN x[0]
    DIRECTION INPUT ;
    USE SIGNAL ;
    PORT
      LAYER M4 ;
        RECT  0 75.888 0.084 75.912 ;
    END
  END x[0]
  PIN x[100]
    DIRECTION INPUT ;
    USE SIGNAL ;
    PORT
      LAYER M4 ;
        RECT  0 80.688 0.084 80.712 ;
    END
  END x[100]
  PIN x[101]
    DIRECTION INPUT ;
    USE SIGNAL ;
    PORT
      LAYER M4 ;
        RECT  0 80.736 0.084 80.76 ;
    END
  END x[101]
  PIN x[102]
    DIRECTION INPUT ;
    USE SIGNAL ;
    PORT
      LAYER M4 ;
        RECT  0 80.784 0.084 80.808 ;
    END
  END x[102]
  PIN x[103]
    DIRECTION INPUT ;
    USE SIGNAL ;
    PORT
      LAYER M4 ;
        RECT  0 80.832 0.084 80.856 ;
    END
  END x[103]
  PIN x[104]
    DIRECTION INPUT ;
    USE SIGNAL ;
    PORT
      LAYER M4 ;
        RECT  0 80.88 0.084 80.904 ;
    END
  END x[104]
  PIN x[105]
    DIRECTION INPUT ;
    USE SIGNAL ;
    PORT
      LAYER M4 ;
        RECT  0 80.928 0.084 80.952 ;
    END
  END x[105]
  PIN x[106]
    DIRECTION INPUT ;
    USE SIGNAL ;
    PORT
      LAYER M4 ;
        RECT  0 80.976 0.084 81 ;
    END
  END x[106]
  PIN x[107]
    DIRECTION INPUT ;
    USE SIGNAL ;
    PORT
      LAYER M4 ;
        RECT  0 81.024 0.084 81.048 ;
    END
  END x[107]
  PIN x[108]
    DIRECTION INPUT ;
    USE SIGNAL ;
    PORT
      LAYER M4 ;
        RECT  0 81.072 0.084 81.096 ;
    END
  END x[108]
  PIN x[109]
    DIRECTION INPUT ;
    USE SIGNAL ;
    PORT
      LAYER M4 ;
        RECT  0 81.12 0.084 81.144 ;
    END
  END x[109]
  PIN x[10]
    DIRECTION INPUT ;
    USE SIGNAL ;
    PORT
      LAYER M4 ;
        RECT  0 76.368 0.084 76.392 ;
    END
  END x[10]
  PIN x[110]
    DIRECTION INPUT ;
    USE SIGNAL ;
    PORT
      LAYER M4 ;
        RECT  0 81.168 0.084 81.192 ;
    END
  END x[110]
  PIN x[111]
    DIRECTION INPUT ;
    USE SIGNAL ;
    PORT
      LAYER M4 ;
        RECT  0 81.216 0.084 81.24 ;
    END
  END x[111]
  PIN x[112]
    DIRECTION INPUT ;
    USE SIGNAL ;
    PORT
      LAYER M4 ;
        RECT  0 81.264 0.084 81.288 ;
    END
  END x[112]
  PIN x[113]
    DIRECTION INPUT ;
    USE SIGNAL ;
    PORT
      LAYER M4 ;
        RECT  0 81.312 0.084 81.336 ;
    END
  END x[113]
  PIN x[114]
    DIRECTION INPUT ;
    USE SIGNAL ;
    PORT
      LAYER M4 ;
        RECT  0 81.36 0.084 81.384 ;
    END
  END x[114]
  PIN x[115]
    DIRECTION INPUT ;
    USE SIGNAL ;
    PORT
      LAYER M4 ;
        RECT  0 81.408 0.084 81.432 ;
    END
  END x[115]
  PIN x[116]
    DIRECTION INPUT ;
    USE SIGNAL ;
    PORT
      LAYER M4 ;
        RECT  0 81.456 0.084 81.48 ;
    END
  END x[116]
  PIN x[117]
    DIRECTION INPUT ;
    USE SIGNAL ;
    PORT
      LAYER M4 ;
        RECT  0 81.504 0.084 81.528 ;
    END
  END x[117]
  PIN x[118]
    DIRECTION INPUT ;
    USE SIGNAL ;
    PORT
      LAYER M4 ;
        RECT  0 81.552 0.084 81.576 ;
    END
  END x[118]
  PIN x[119]
    DIRECTION INPUT ;
    USE SIGNAL ;
    PORT
      LAYER M4 ;
        RECT  0 81.6 0.084 81.624 ;
    END
  END x[119]
  PIN x[11]
    DIRECTION INPUT ;
    USE SIGNAL ;
    PORT
      LAYER M4 ;
        RECT  0 76.416 0.084 76.44 ;
    END
  END x[11]
  PIN x[120]
    DIRECTION INPUT ;
    USE SIGNAL ;
    PORT
      LAYER M4 ;
        RECT  0 81.648 0.084 81.672 ;
    END
  END x[120]
  PIN x[121]
    DIRECTION INPUT ;
    USE SIGNAL ;
    PORT
      LAYER M4 ;
        RECT  0 81.696 0.084 81.72 ;
    END
  END x[121]
  PIN x[122]
    DIRECTION INPUT ;
    USE SIGNAL ;
    PORT
      LAYER M4 ;
        RECT  0 81.744 0.084 81.768 ;
    END
  END x[122]
  PIN x[123]
    DIRECTION INPUT ;
    USE SIGNAL ;
    PORT
      LAYER M4 ;
        RECT  0 81.792 0.084 81.816 ;
    END
  END x[123]
  PIN x[124]
    DIRECTION INPUT ;
    USE SIGNAL ;
    PORT
      LAYER M4 ;
        RECT  0 81.84 0.084 81.864 ;
    END
  END x[124]
  PIN x[125]
    DIRECTION INPUT ;
    USE SIGNAL ;
    PORT
      LAYER M4 ;
        RECT  0 81.888 0.084 81.912 ;
    END
  END x[125]
  PIN x[126]
    DIRECTION INPUT ;
    USE SIGNAL ;
    PORT
      LAYER M4 ;
        RECT  0 81.936 0.084 81.96 ;
    END
  END x[126]
  PIN x[127]
    DIRECTION INPUT ;
    USE SIGNAL ;
    PORT
      LAYER M4 ;
        RECT  0 81.984 0.084 82.008 ;
    END
  END x[127]
  PIN x[128]
    DIRECTION INPUT ;
    USE SIGNAL ;
    PORT
      LAYER M4 ;
        RECT  0 82.032 0.084 82.056 ;
    END
  END x[128]
  PIN x[129]
    DIRECTION INPUT ;
    USE SIGNAL ;
    PORT
      LAYER M4 ;
        RECT  0 82.08 0.084 82.104 ;
    END
  END x[129]
  PIN x[12]
    DIRECTION INPUT ;
    USE SIGNAL ;
    PORT
      LAYER M4 ;
        RECT  0 76.464 0.084 76.488 ;
    END
  END x[12]
  PIN x[130]
    DIRECTION INPUT ;
    USE SIGNAL ;
    PORT
      LAYER M4 ;
        RECT  0 82.128 0.084 82.152 ;
    END
  END x[130]
  PIN x[131]
    DIRECTION INPUT ;
    USE SIGNAL ;
    PORT
      LAYER M4 ;
        RECT  0 82.176 0.084 82.2 ;
    END
  END x[131]
  PIN x[132]
    DIRECTION INPUT ;
    USE SIGNAL ;
    PORT
      LAYER M4 ;
        RECT  0 82.224 0.084 82.248 ;
    END
  END x[132]
  PIN x[133]
    DIRECTION INPUT ;
    USE SIGNAL ;
    PORT
      LAYER M4 ;
        RECT  0 82.272 0.084 82.296 ;
    END
  END x[133]
  PIN x[134]
    DIRECTION INPUT ;
    USE SIGNAL ;
    PORT
      LAYER M4 ;
        RECT  0 82.32 0.084 82.344 ;
    END
  END x[134]
  PIN x[135]
    DIRECTION INPUT ;
    USE SIGNAL ;
    PORT
      LAYER M4 ;
        RECT  0 82.368 0.084 82.392 ;
    END
  END x[135]
  PIN x[136]
    DIRECTION INPUT ;
    USE SIGNAL ;
    PORT
      LAYER M4 ;
        RECT  0 82.416 0.084 82.44 ;
    END
  END x[136]
  PIN x[137]
    DIRECTION INPUT ;
    USE SIGNAL ;
    PORT
      LAYER M4 ;
        RECT  0 82.464 0.084 82.488 ;
    END
  END x[137]
  PIN x[138]
    DIRECTION INPUT ;
    USE SIGNAL ;
    PORT
      LAYER M4 ;
        RECT  0 82.512 0.084 82.536 ;
    END
  END x[138]
  PIN x[139]
    DIRECTION INPUT ;
    USE SIGNAL ;
    PORT
      LAYER M4 ;
        RECT  0 82.56 0.084 82.584 ;
    END
  END x[139]
  PIN x[13]
    DIRECTION INPUT ;
    USE SIGNAL ;
    PORT
      LAYER M4 ;
        RECT  0 76.512 0.084 76.536 ;
    END
  END x[13]
  PIN x[140]
    DIRECTION INPUT ;
    USE SIGNAL ;
    PORT
      LAYER M4 ;
        RECT  0 82.608 0.084 82.632 ;
    END
  END x[140]
  PIN x[141]
    DIRECTION INPUT ;
    USE SIGNAL ;
    PORT
      LAYER M4 ;
        RECT  0 82.656 0.084 82.68 ;
    END
  END x[141]
  PIN x[142]
    DIRECTION INPUT ;
    USE SIGNAL ;
    PORT
      LAYER M4 ;
        RECT  0 82.704 0.084 82.728 ;
    END
  END x[142]
  PIN x[143]
    DIRECTION INPUT ;
    USE SIGNAL ;
    PORT
      LAYER M4 ;
        RECT  0 82.752 0.084 82.776 ;
    END
  END x[143]
  PIN x[144]
    DIRECTION INPUT ;
    USE SIGNAL ;
    PORT
      LAYER M4 ;
        RECT  0 82.8 0.084 82.824 ;
    END
  END x[144]
  PIN x[145]
    DIRECTION INPUT ;
    USE SIGNAL ;
    PORT
      LAYER M4 ;
        RECT  0 82.848 0.084 82.872 ;
    END
  END x[145]
  PIN x[146]
    DIRECTION INPUT ;
    USE SIGNAL ;
    PORT
      LAYER M4 ;
        RECT  0 82.896 0.084 82.92 ;
    END
  END x[146]
  PIN x[147]
    DIRECTION INPUT ;
    USE SIGNAL ;
    PORT
      LAYER M4 ;
        RECT  0 82.944 0.084 82.968 ;
    END
  END x[147]
  PIN x[148]
    DIRECTION INPUT ;
    USE SIGNAL ;
    PORT
      LAYER M4 ;
        RECT  0 82.992 0.084 83.016 ;
    END
  END x[148]
  PIN x[149]
    DIRECTION INPUT ;
    USE SIGNAL ;
    PORT
      LAYER M4 ;
        RECT  0 83.04 0.084 83.064 ;
    END
  END x[149]
  PIN x[14]
    DIRECTION INPUT ;
    USE SIGNAL ;
    PORT
      LAYER M4 ;
        RECT  0 76.56 0.084 76.584 ;
    END
  END x[14]
  PIN x[150]
    DIRECTION INPUT ;
    USE SIGNAL ;
    PORT
      LAYER M4 ;
        RECT  0 83.088 0.084 83.112 ;
    END
  END x[150]
  PIN x[151]
    DIRECTION INPUT ;
    USE SIGNAL ;
    PORT
      LAYER M4 ;
        RECT  0 83.136 0.084 83.16 ;
    END
  END x[151]
  PIN x[152]
    DIRECTION INPUT ;
    USE SIGNAL ;
    PORT
      LAYER M4 ;
        RECT  0 83.184 0.084 83.208 ;
    END
  END x[152]
  PIN x[153]
    DIRECTION INPUT ;
    USE SIGNAL ;
    PORT
      LAYER M4 ;
        RECT  0 83.232 0.084 83.256 ;
    END
  END x[153]
  PIN x[154]
    DIRECTION INPUT ;
    USE SIGNAL ;
    PORT
      LAYER M4 ;
        RECT  0 83.28 0.084 83.304 ;
    END
  END x[154]
  PIN x[155]
    DIRECTION INPUT ;
    USE SIGNAL ;
    PORT
      LAYER M4 ;
        RECT  0 83.328 0.084 83.352 ;
    END
  END x[155]
  PIN x[156]
    DIRECTION INPUT ;
    USE SIGNAL ;
    PORT
      LAYER M4 ;
        RECT  0 83.376 0.084 83.4 ;
    END
  END x[156]
  PIN x[157]
    DIRECTION INPUT ;
    USE SIGNAL ;
    PORT
      LAYER M4 ;
        RECT  0 83.424 0.084 83.448 ;
    END
  END x[157]
  PIN x[158]
    DIRECTION INPUT ;
    USE SIGNAL ;
    PORT
      LAYER M4 ;
        RECT  0 83.472 0.084 83.496 ;
    END
  END x[158]
  PIN x[159]
    DIRECTION INPUT ;
    USE SIGNAL ;
    PORT
      LAYER M4 ;
        RECT  0 83.52 0.084 83.544 ;
    END
  END x[159]
  PIN x[15]
    DIRECTION INPUT ;
    USE SIGNAL ;
    PORT
      LAYER M4 ;
        RECT  0 76.608 0.084 76.632 ;
    END
  END x[15]
  PIN x[160]
    DIRECTION INPUT ;
    USE SIGNAL ;
    PORT
      LAYER M4 ;
        RECT  0 83.568 0.084 83.592 ;
    END
  END x[160]
  PIN x[161]
    DIRECTION INPUT ;
    USE SIGNAL ;
    PORT
      LAYER M4 ;
        RECT  0 83.616 0.084 83.64 ;
    END
  END x[161]
  PIN x[162]
    DIRECTION INPUT ;
    USE SIGNAL ;
    PORT
      LAYER M4 ;
        RECT  0 83.664 0.084 83.688 ;
    END
  END x[162]
  PIN x[163]
    DIRECTION INPUT ;
    USE SIGNAL ;
    PORT
      LAYER M4 ;
        RECT  0 83.712 0.084 83.736 ;
    END
  END x[163]
  PIN x[164]
    DIRECTION INPUT ;
    USE SIGNAL ;
    PORT
      LAYER M4 ;
        RECT  0 83.76 0.084 83.784 ;
    END
  END x[164]
  PIN x[165]
    DIRECTION INPUT ;
    USE SIGNAL ;
    PORT
      LAYER M4 ;
        RECT  0 83.808 0.084 83.832 ;
    END
  END x[165]
  PIN x[166]
    DIRECTION INPUT ;
    USE SIGNAL ;
    PORT
      LAYER M4 ;
        RECT  0 83.856 0.084 83.88 ;
    END
  END x[166]
  PIN x[167]
    DIRECTION INPUT ;
    USE SIGNAL ;
    PORT
      LAYER M4 ;
        RECT  0 83.904 0.084 83.928 ;
    END
  END x[167]
  PIN x[168]
    DIRECTION INPUT ;
    USE SIGNAL ;
    PORT
      LAYER M4 ;
        RECT  0 83.952 0.084 83.976 ;
    END
  END x[168]
  PIN x[169]
    DIRECTION INPUT ;
    USE SIGNAL ;
    PORT
      LAYER M4 ;
        RECT  0 84 0.084 84.024 ;
    END
  END x[169]
  PIN x[16]
    DIRECTION INPUT ;
    USE SIGNAL ;
    PORT
      LAYER M4 ;
        RECT  0 76.656 0.084 76.68 ;
    END
  END x[16]
  PIN x[170]
    DIRECTION INPUT ;
    USE SIGNAL ;
    PORT
      LAYER M4 ;
        RECT  0 84.048 0.084 84.072 ;
    END
  END x[170]
  PIN x[171]
    DIRECTION INPUT ;
    USE SIGNAL ;
    PORT
      LAYER M4 ;
        RECT  0 84.096 0.084 84.12 ;
    END
  END x[171]
  PIN x[172]
    DIRECTION INPUT ;
    USE SIGNAL ;
    PORT
      LAYER M4 ;
        RECT  0 84.144 0.084 84.168 ;
    END
  END x[172]
  PIN x[173]
    DIRECTION INPUT ;
    USE SIGNAL ;
    PORT
      LAYER M4 ;
        RECT  0 84.192 0.084 84.216 ;
    END
  END x[173]
  PIN x[174]
    DIRECTION INPUT ;
    USE SIGNAL ;
    PORT
      LAYER M4 ;
        RECT  0 84.24 0.084 84.264 ;
    END
  END x[174]
  PIN x[175]
    DIRECTION INPUT ;
    USE SIGNAL ;
    PORT
      LAYER M4 ;
        RECT  0 84.288 0.084 84.312 ;
    END
  END x[175]
  PIN x[176]
    DIRECTION INPUT ;
    USE SIGNAL ;
    PORT
      LAYER M4 ;
        RECT  0 84.336 0.084 84.36 ;
    END
  END x[176]
  PIN x[177]
    DIRECTION INPUT ;
    USE SIGNAL ;
    PORT
      LAYER M4 ;
        RECT  0 84.384 0.084 84.408 ;
    END
  END x[177]
  PIN x[178]
    DIRECTION INPUT ;
    USE SIGNAL ;
    PORT
      LAYER M4 ;
        RECT  0 84.432 0.084 84.456 ;
    END
  END x[178]
  PIN x[179]
    DIRECTION INPUT ;
    USE SIGNAL ;
    PORT
      LAYER M4 ;
        RECT  0 84.48 0.084 84.504 ;
    END
  END x[179]
  PIN x[17]
    DIRECTION INPUT ;
    USE SIGNAL ;
    PORT
      LAYER M4 ;
        RECT  0 76.704 0.084 76.728 ;
    END
  END x[17]
  PIN x[180]
    DIRECTION INPUT ;
    USE SIGNAL ;
    PORT
      LAYER M4 ;
        RECT  0 84.528 0.084 84.552 ;
    END
  END x[180]
  PIN x[181]
    DIRECTION INPUT ;
    USE SIGNAL ;
    PORT
      LAYER M4 ;
        RECT  0 84.576 0.084 84.6 ;
    END
  END x[181]
  PIN x[182]
    DIRECTION INPUT ;
    USE SIGNAL ;
    PORT
      LAYER M4 ;
        RECT  0 84.624 0.084 84.648 ;
    END
  END x[182]
  PIN x[183]
    DIRECTION INPUT ;
    USE SIGNAL ;
    PORT
      LAYER M4 ;
        RECT  0 84.672 0.084 84.696 ;
    END
  END x[183]
  PIN x[184]
    DIRECTION INPUT ;
    USE SIGNAL ;
    PORT
      LAYER M4 ;
        RECT  0 84.72 0.084 84.744 ;
    END
  END x[184]
  PIN x[185]
    DIRECTION INPUT ;
    USE SIGNAL ;
    PORT
      LAYER M4 ;
        RECT  0 84.768 0.084 84.792 ;
    END
  END x[185]
  PIN x[186]
    DIRECTION INPUT ;
    USE SIGNAL ;
    PORT
      LAYER M4 ;
        RECT  0 84.816 0.084 84.84 ;
    END
  END x[186]
  PIN x[187]
    DIRECTION INPUT ;
    USE SIGNAL ;
    PORT
      LAYER M4 ;
        RECT  0 84.864 0.084 84.888 ;
    END
  END x[187]
  PIN x[188]
    DIRECTION INPUT ;
    USE SIGNAL ;
    PORT
      LAYER M4 ;
        RECT  0 84.912 0.084 84.936 ;
    END
  END x[188]
  PIN x[189]
    DIRECTION INPUT ;
    USE SIGNAL ;
    PORT
      LAYER M4 ;
        RECT  0 84.96 0.084 84.984 ;
    END
  END x[189]
  PIN x[18]
    DIRECTION INPUT ;
    USE SIGNAL ;
    PORT
      LAYER M4 ;
        RECT  0 76.752 0.084 76.776 ;
    END
  END x[18]
  PIN x[190]
    DIRECTION INPUT ;
    USE SIGNAL ;
    PORT
      LAYER M4 ;
        RECT  0 85.008 0.084 85.032 ;
    END
  END x[190]
  PIN x[191]
    DIRECTION INPUT ;
    USE SIGNAL ;
    PORT
      LAYER M4 ;
        RECT  0 85.056 0.084 85.08 ;
    END
  END x[191]
  PIN x[192]
    DIRECTION INPUT ;
    USE SIGNAL ;
    PORT
      LAYER M4 ;
        RECT  0 85.104 0.084 85.128 ;
    END
  END x[192]
  PIN x[193]
    DIRECTION INPUT ;
    USE SIGNAL ;
    PORT
      LAYER M4 ;
        RECT  0 85.152 0.084 85.176 ;
    END
  END x[193]
  PIN x[194]
    DIRECTION INPUT ;
    USE SIGNAL ;
    PORT
      LAYER M4 ;
        RECT  0 85.2 0.084 85.224 ;
    END
  END x[194]
  PIN x[195]
    DIRECTION INPUT ;
    USE SIGNAL ;
    PORT
      LAYER M4 ;
        RECT  0 85.248 0.084 85.272 ;
    END
  END x[195]
  PIN x[196]
    DIRECTION INPUT ;
    USE SIGNAL ;
    PORT
      LAYER M4 ;
        RECT  0 85.296 0.084 85.32 ;
    END
  END x[196]
  PIN x[197]
    DIRECTION INPUT ;
    USE SIGNAL ;
    PORT
      LAYER M4 ;
        RECT  0 85.344 0.084 85.368 ;
    END
  END x[197]
  PIN x[198]
    DIRECTION INPUT ;
    USE SIGNAL ;
    PORT
      LAYER M4 ;
        RECT  0 85.392 0.084 85.416 ;
    END
  END x[198]
  PIN x[199]
    DIRECTION INPUT ;
    USE SIGNAL ;
    PORT
      LAYER M4 ;
        RECT  0 85.44 0.084 85.464 ;
    END
  END x[199]
  PIN x[19]
    DIRECTION INPUT ;
    USE SIGNAL ;
    PORT
      LAYER M4 ;
        RECT  0 76.8 0.084 76.824 ;
    END
  END x[19]
  PIN x[1]
    DIRECTION INPUT ;
    USE SIGNAL ;
    PORT
      LAYER M4 ;
        RECT  0 75.936 0.084 75.96 ;
    END
  END x[1]
  PIN x[200]
    DIRECTION INPUT ;
    USE SIGNAL ;
    PORT
      LAYER M4 ;
        RECT  0 85.488 0.084 85.512 ;
    END
  END x[200]
  PIN x[201]
    DIRECTION INPUT ;
    USE SIGNAL ;
    PORT
      LAYER M4 ;
        RECT  0 85.536 0.084 85.56 ;
    END
  END x[201]
  PIN x[202]
    DIRECTION INPUT ;
    USE SIGNAL ;
    PORT
      LAYER M4 ;
        RECT  0 85.584 0.084 85.608 ;
    END
  END x[202]
  PIN x[203]
    DIRECTION INPUT ;
    USE SIGNAL ;
    PORT
      LAYER M4 ;
        RECT  0 85.632 0.084 85.656 ;
    END
  END x[203]
  PIN x[204]
    DIRECTION INPUT ;
    USE SIGNAL ;
    PORT
      LAYER M4 ;
        RECT  0 85.68 0.084 85.704 ;
    END
  END x[204]
  PIN x[205]
    DIRECTION INPUT ;
    USE SIGNAL ;
    PORT
      LAYER M4 ;
        RECT  0 85.728 0.084 85.752 ;
    END
  END x[205]
  PIN x[206]
    DIRECTION INPUT ;
    USE SIGNAL ;
    PORT
      LAYER M4 ;
        RECT  0 85.776 0.084 85.8 ;
    END
  END x[206]
  PIN x[207]
    DIRECTION INPUT ;
    USE SIGNAL ;
    PORT
      LAYER M4 ;
        RECT  0 85.824 0.084 85.848 ;
    END
  END x[207]
  PIN x[208]
    DIRECTION INPUT ;
    USE SIGNAL ;
    PORT
      LAYER M4 ;
        RECT  0 85.872 0.084 85.896 ;
    END
  END x[208]
  PIN x[209]
    DIRECTION INPUT ;
    USE SIGNAL ;
    PORT
      LAYER M4 ;
        RECT  0 85.92 0.084 85.944 ;
    END
  END x[209]
  PIN x[20]
    DIRECTION INPUT ;
    USE SIGNAL ;
    PORT
      LAYER M4 ;
        RECT  0 76.848 0.084 76.872 ;
    END
  END x[20]
  PIN x[210]
    DIRECTION INPUT ;
    USE SIGNAL ;
    PORT
      LAYER M4 ;
        RECT  0 85.968 0.084 85.992 ;
    END
  END x[210]
  PIN x[211]
    DIRECTION INPUT ;
    USE SIGNAL ;
    PORT
      LAYER M4 ;
        RECT  0 86.016 0.084 86.04 ;
    END
  END x[211]
  PIN x[212]
    DIRECTION INPUT ;
    USE SIGNAL ;
    PORT
      LAYER M4 ;
        RECT  0 86.064 0.084 86.088 ;
    END
  END x[212]
  PIN x[213]
    DIRECTION INPUT ;
    USE SIGNAL ;
    PORT
      LAYER M4 ;
        RECT  0 86.112 0.084 86.136 ;
    END
  END x[213]
  PIN x[214]
    DIRECTION INPUT ;
    USE SIGNAL ;
    PORT
      LAYER M4 ;
        RECT  0 86.16 0.084 86.184 ;
    END
  END x[214]
  PIN x[215]
    DIRECTION INPUT ;
    USE SIGNAL ;
    PORT
      LAYER M4 ;
        RECT  0 86.208 0.084 86.232 ;
    END
  END x[215]
  PIN x[216]
    DIRECTION INPUT ;
    USE SIGNAL ;
    PORT
      LAYER M4 ;
        RECT  0 86.256 0.084 86.28 ;
    END
  END x[216]
  PIN x[217]
    DIRECTION INPUT ;
    USE SIGNAL ;
    PORT
      LAYER M4 ;
        RECT  0 86.304 0.084 86.328 ;
    END
  END x[217]
  PIN x[218]
    DIRECTION INPUT ;
    USE SIGNAL ;
    PORT
      LAYER M4 ;
        RECT  0 86.352 0.084 86.376 ;
    END
  END x[218]
  PIN x[219]
    DIRECTION INPUT ;
    USE SIGNAL ;
    PORT
      LAYER M4 ;
        RECT  0 86.4 0.084 86.424 ;
    END
  END x[219]
  PIN x[21]
    DIRECTION INPUT ;
    USE SIGNAL ;
    PORT
      LAYER M4 ;
        RECT  0 76.896 0.084 76.92 ;
    END
  END x[21]
  PIN x[220]
    DIRECTION INPUT ;
    USE SIGNAL ;
    PORT
      LAYER M4 ;
        RECT  0 86.448 0.084 86.472 ;
    END
  END x[220]
  PIN x[221]
    DIRECTION INPUT ;
    USE SIGNAL ;
    PORT
      LAYER M4 ;
        RECT  0 86.496 0.084 86.52 ;
    END
  END x[221]
  PIN x[222]
    DIRECTION INPUT ;
    USE SIGNAL ;
    PORT
      LAYER M4 ;
        RECT  0 86.544 0.084 86.568 ;
    END
  END x[222]
  PIN x[223]
    DIRECTION INPUT ;
    USE SIGNAL ;
    PORT
      LAYER M4 ;
        RECT  0 86.592 0.084 86.616 ;
    END
  END x[223]
  PIN x[224]
    DIRECTION INPUT ;
    USE SIGNAL ;
    PORT
      LAYER M4 ;
        RECT  0 86.64 0.084 86.664 ;
    END
  END x[224]
  PIN x[225]
    DIRECTION INPUT ;
    USE SIGNAL ;
    PORT
      LAYER M4 ;
        RECT  0 86.688 0.084 86.712 ;
    END
  END x[225]
  PIN x[226]
    DIRECTION INPUT ;
    USE SIGNAL ;
    PORT
      LAYER M4 ;
        RECT  0 86.736 0.084 86.76 ;
    END
  END x[226]
  PIN x[227]
    DIRECTION INPUT ;
    USE SIGNAL ;
    PORT
      LAYER M4 ;
        RECT  0 86.784 0.084 86.808 ;
    END
  END x[227]
  PIN x[228]
    DIRECTION INPUT ;
    USE SIGNAL ;
    PORT
      LAYER M4 ;
        RECT  0 86.832 0.084 86.856 ;
    END
  END x[228]
  PIN x[229]
    DIRECTION INPUT ;
    USE SIGNAL ;
    PORT
      LAYER M4 ;
        RECT  0 86.88 0.084 86.904 ;
    END
  END x[229]
  PIN x[22]
    DIRECTION INPUT ;
    USE SIGNAL ;
    PORT
      LAYER M4 ;
        RECT  0 76.944 0.084 76.968 ;
    END
  END x[22]
  PIN x[230]
    DIRECTION INPUT ;
    USE SIGNAL ;
    PORT
      LAYER M4 ;
        RECT  0 86.928 0.084 86.952 ;
    END
  END x[230]
  PIN x[231]
    DIRECTION INPUT ;
    USE SIGNAL ;
    PORT
      LAYER M4 ;
        RECT  0 86.976 0.084 87 ;
    END
  END x[231]
  PIN x[232]
    DIRECTION INPUT ;
    USE SIGNAL ;
    PORT
      LAYER M4 ;
        RECT  0 87.024 0.084 87.048 ;
    END
  END x[232]
  PIN x[233]
    DIRECTION INPUT ;
    USE SIGNAL ;
    PORT
      LAYER M4 ;
        RECT  0 87.072 0.084 87.096 ;
    END
  END x[233]
  PIN x[234]
    DIRECTION INPUT ;
    USE SIGNAL ;
    PORT
      LAYER M4 ;
        RECT  0 87.12 0.084 87.144 ;
    END
  END x[234]
  PIN x[235]
    DIRECTION INPUT ;
    USE SIGNAL ;
    PORT
      LAYER M4 ;
        RECT  0 87.168 0.084 87.192 ;
    END
  END x[235]
  PIN x[236]
    DIRECTION INPUT ;
    USE SIGNAL ;
    PORT
      LAYER M4 ;
        RECT  0 87.216 0.084 87.24 ;
    END
  END x[236]
  PIN x[237]
    DIRECTION INPUT ;
    USE SIGNAL ;
    PORT
      LAYER M4 ;
        RECT  0 87.264 0.084 87.288 ;
    END
  END x[237]
  PIN x[238]
    DIRECTION INPUT ;
    USE SIGNAL ;
    PORT
      LAYER M4 ;
        RECT  0 87.312 0.084 87.336 ;
    END
  END x[238]
  PIN x[239]
    DIRECTION INPUT ;
    USE SIGNAL ;
    PORT
      LAYER M4 ;
        RECT  0 87.36 0.084 87.384 ;
    END
  END x[239]
  PIN x[23]
    DIRECTION INPUT ;
    USE SIGNAL ;
    PORT
      LAYER M4 ;
        RECT  0 76.992 0.084 77.016 ;
    END
  END x[23]
  PIN x[240]
    DIRECTION INPUT ;
    USE SIGNAL ;
    PORT
      LAYER M4 ;
        RECT  0 87.408 0.084 87.432 ;
    END
  END x[240]
  PIN x[241]
    DIRECTION INPUT ;
    USE SIGNAL ;
    PORT
      LAYER M4 ;
        RECT  0 87.456 0.084 87.48 ;
    END
  END x[241]
  PIN x[242]
    DIRECTION INPUT ;
    USE SIGNAL ;
    PORT
      LAYER M4 ;
        RECT  0 87.504 0.084 87.528 ;
    END
  END x[242]
  PIN x[243]
    DIRECTION INPUT ;
    USE SIGNAL ;
    PORT
      LAYER M4 ;
        RECT  0 87.552 0.084 87.576 ;
    END
  END x[243]
  PIN x[244]
    DIRECTION INPUT ;
    USE SIGNAL ;
    PORT
      LAYER M4 ;
        RECT  0 87.6 0.084 87.624 ;
    END
  END x[244]
  PIN x[245]
    DIRECTION INPUT ;
    USE SIGNAL ;
    PORT
      LAYER M4 ;
        RECT  0 87.648 0.084 87.672 ;
    END
  END x[245]
  PIN x[246]
    DIRECTION INPUT ;
    USE SIGNAL ;
    PORT
      LAYER M4 ;
        RECT  0 87.696 0.084 87.72 ;
    END
  END x[246]
  PIN x[247]
    DIRECTION INPUT ;
    USE SIGNAL ;
    PORT
      LAYER M4 ;
        RECT  0 87.744 0.084 87.768 ;
    END
  END x[247]
  PIN x[248]
    DIRECTION INPUT ;
    USE SIGNAL ;
    PORT
      LAYER M4 ;
        RECT  0 87.792 0.084 87.816 ;
    END
  END x[248]
  PIN x[249]
    DIRECTION INPUT ;
    USE SIGNAL ;
    PORT
      LAYER M4 ;
        RECT  0 87.84 0.084 87.864 ;
    END
  END x[249]
  PIN x[24]
    DIRECTION INPUT ;
    USE SIGNAL ;
    PORT
      LAYER M4 ;
        RECT  0 77.04 0.084 77.064 ;
    END
  END x[24]
  PIN x[250]
    DIRECTION INPUT ;
    USE SIGNAL ;
    PORT
      LAYER M4 ;
        RECT  0 87.888 0.084 87.912 ;
    END
  END x[250]
  PIN x[251]
    DIRECTION INPUT ;
    USE SIGNAL ;
    PORT
      LAYER M4 ;
        RECT  0 87.936 0.084 87.96 ;
    END
  END x[251]
  PIN x[252]
    DIRECTION INPUT ;
    USE SIGNAL ;
    PORT
      LAYER M4 ;
        RECT  0 87.984 0.084 88.008 ;
    END
  END x[252]
  PIN x[253]
    DIRECTION INPUT ;
    USE SIGNAL ;
    PORT
      LAYER M4 ;
        RECT  0 88.032 0.084 88.056 ;
    END
  END x[253]
  PIN x[254]
    DIRECTION INPUT ;
    USE SIGNAL ;
    PORT
      LAYER M4 ;
        RECT  0 88.08 0.084 88.104 ;
    END
  END x[254]
  PIN x[255]
    DIRECTION INPUT ;
    USE SIGNAL ;
    PORT
      LAYER M4 ;
        RECT  0 88.128 0.084 88.152 ;
    END
  END x[255]
  PIN x[25]
    DIRECTION INPUT ;
    USE SIGNAL ;
    PORT
      LAYER M4 ;
        RECT  0 77.088 0.084 77.112 ;
    END
  END x[25]
  PIN x[26]
    DIRECTION INPUT ;
    USE SIGNAL ;
    PORT
      LAYER M4 ;
        RECT  0 77.136 0.084 77.16 ;
    END
  END x[26]
  PIN x[27]
    DIRECTION INPUT ;
    USE SIGNAL ;
    PORT
      LAYER M4 ;
        RECT  0 77.184 0.084 77.208 ;
    END
  END x[27]
  PIN x[28]
    DIRECTION INPUT ;
    USE SIGNAL ;
    PORT
      LAYER M4 ;
        RECT  0 77.232 0.084 77.256 ;
    END
  END x[28]
  PIN x[29]
    DIRECTION INPUT ;
    USE SIGNAL ;
    PORT
      LAYER M4 ;
        RECT  0 77.28 0.084 77.304 ;
    END
  END x[29]
  PIN x[2]
    DIRECTION INPUT ;
    USE SIGNAL ;
    PORT
      LAYER M4 ;
        RECT  0 75.984 0.084 76.008 ;
    END
  END x[2]
  PIN x[30]
    DIRECTION INPUT ;
    USE SIGNAL ;
    PORT
      LAYER M4 ;
        RECT  0 77.328 0.084 77.352 ;
    END
  END x[30]
  PIN x[31]
    DIRECTION INPUT ;
    USE SIGNAL ;
    PORT
      LAYER M4 ;
        RECT  0 77.376 0.084 77.4 ;
    END
  END x[31]
  PIN x[32]
    DIRECTION INPUT ;
    USE SIGNAL ;
    PORT
      LAYER M4 ;
        RECT  0 77.424 0.084 77.448 ;
    END
  END x[32]
  PIN x[33]
    DIRECTION INPUT ;
    USE SIGNAL ;
    PORT
      LAYER M4 ;
        RECT  0 77.472 0.084 77.496 ;
    END
  END x[33]
  PIN x[34]
    DIRECTION INPUT ;
    USE SIGNAL ;
    PORT
      LAYER M4 ;
        RECT  0 77.52 0.084 77.544 ;
    END
  END x[34]
  PIN x[35]
    DIRECTION INPUT ;
    USE SIGNAL ;
    PORT
      LAYER M4 ;
        RECT  0 77.568 0.084 77.592 ;
    END
  END x[35]
  PIN x[36]
    DIRECTION INPUT ;
    USE SIGNAL ;
    PORT
      LAYER M4 ;
        RECT  0 77.616 0.084 77.64 ;
    END
  END x[36]
  PIN x[37]
    DIRECTION INPUT ;
    USE SIGNAL ;
    PORT
      LAYER M4 ;
        RECT  0 77.664 0.084 77.688 ;
    END
  END x[37]
  PIN x[38]
    DIRECTION INPUT ;
    USE SIGNAL ;
    PORT
      LAYER M4 ;
        RECT  0 77.712 0.084 77.736 ;
    END
  END x[38]
  PIN x[39]
    DIRECTION INPUT ;
    USE SIGNAL ;
    PORT
      LAYER M4 ;
        RECT  0 77.76 0.084 77.784 ;
    END
  END x[39]
  PIN x[3]
    DIRECTION INPUT ;
    USE SIGNAL ;
    PORT
      LAYER M4 ;
        RECT  0 76.032 0.084 76.056 ;
    END
  END x[3]
  PIN x[40]
    DIRECTION INPUT ;
    USE SIGNAL ;
    PORT
      LAYER M4 ;
        RECT  0 77.808 0.084 77.832 ;
    END
  END x[40]
  PIN x[41]
    DIRECTION INPUT ;
    USE SIGNAL ;
    PORT
      LAYER M4 ;
        RECT  0 77.856 0.084 77.88 ;
    END
  END x[41]
  PIN x[42]
    DIRECTION INPUT ;
    USE SIGNAL ;
    PORT
      LAYER M4 ;
        RECT  0 77.904 0.084 77.928 ;
    END
  END x[42]
  PIN x[43]
    DIRECTION INPUT ;
    USE SIGNAL ;
    PORT
      LAYER M4 ;
        RECT  0 77.952 0.084 77.976 ;
    END
  END x[43]
  PIN x[44]
    DIRECTION INPUT ;
    USE SIGNAL ;
    PORT
      LAYER M4 ;
        RECT  0 78 0.084 78.024 ;
    END
  END x[44]
  PIN x[45]
    DIRECTION INPUT ;
    USE SIGNAL ;
    PORT
      LAYER M4 ;
        RECT  0 78.048 0.084 78.072 ;
    END
  END x[45]
  PIN x[46]
    DIRECTION INPUT ;
    USE SIGNAL ;
    PORT
      LAYER M4 ;
        RECT  0 78.096 0.084 78.12 ;
    END
  END x[46]
  PIN x[47]
    DIRECTION INPUT ;
    USE SIGNAL ;
    PORT
      LAYER M4 ;
        RECT  0 78.144 0.084 78.168 ;
    END
  END x[47]
  PIN x[48]
    DIRECTION INPUT ;
    USE SIGNAL ;
    PORT
      LAYER M4 ;
        RECT  0 78.192 0.084 78.216 ;
    END
  END x[48]
  PIN x[49]
    DIRECTION INPUT ;
    USE SIGNAL ;
    PORT
      LAYER M4 ;
        RECT  0 78.24 0.084 78.264 ;
    END
  END x[49]
  PIN x[4]
    DIRECTION INPUT ;
    USE SIGNAL ;
    PORT
      LAYER M4 ;
        RECT  0 76.08 0.084 76.104 ;
    END
  END x[4]
  PIN x[50]
    DIRECTION INPUT ;
    USE SIGNAL ;
    PORT
      LAYER M4 ;
        RECT  0 78.288 0.084 78.312 ;
    END
  END x[50]
  PIN x[51]
    DIRECTION INPUT ;
    USE SIGNAL ;
    PORT
      LAYER M4 ;
        RECT  0 78.336 0.084 78.36 ;
    END
  END x[51]
  PIN x[52]
    DIRECTION INPUT ;
    USE SIGNAL ;
    PORT
      LAYER M4 ;
        RECT  0 78.384 0.084 78.408 ;
    END
  END x[52]
  PIN x[53]
    DIRECTION INPUT ;
    USE SIGNAL ;
    PORT
      LAYER M4 ;
        RECT  0 78.432 0.084 78.456 ;
    END
  END x[53]
  PIN x[54]
    DIRECTION INPUT ;
    USE SIGNAL ;
    PORT
      LAYER M4 ;
        RECT  0 78.48 0.084 78.504 ;
    END
  END x[54]
  PIN x[55]
    DIRECTION INPUT ;
    USE SIGNAL ;
    PORT
      LAYER M4 ;
        RECT  0 78.528 0.084 78.552 ;
    END
  END x[55]
  PIN x[56]
    DIRECTION INPUT ;
    USE SIGNAL ;
    PORT
      LAYER M4 ;
        RECT  0 78.576 0.084 78.6 ;
    END
  END x[56]
  PIN x[57]
    DIRECTION INPUT ;
    USE SIGNAL ;
    PORT
      LAYER M4 ;
        RECT  0 78.624 0.084 78.648 ;
    END
  END x[57]
  PIN x[58]
    DIRECTION INPUT ;
    USE SIGNAL ;
    PORT
      LAYER M4 ;
        RECT  0 78.672 0.084 78.696 ;
    END
  END x[58]
  PIN x[59]
    DIRECTION INPUT ;
    USE SIGNAL ;
    PORT
      LAYER M4 ;
        RECT  0 78.72 0.084 78.744 ;
    END
  END x[59]
  PIN x[5]
    DIRECTION INPUT ;
    USE SIGNAL ;
    PORT
      LAYER M4 ;
        RECT  0 76.128 0.084 76.152 ;
    END
  END x[5]
  PIN x[60]
    DIRECTION INPUT ;
    USE SIGNAL ;
    PORT
      LAYER M4 ;
        RECT  0 78.768 0.084 78.792 ;
    END
  END x[60]
  PIN x[61]
    DIRECTION INPUT ;
    USE SIGNAL ;
    PORT
      LAYER M4 ;
        RECT  0 78.816 0.084 78.84 ;
    END
  END x[61]
  PIN x[62]
    DIRECTION INPUT ;
    USE SIGNAL ;
    PORT
      LAYER M4 ;
        RECT  0 78.864 0.084 78.888 ;
    END
  END x[62]
  PIN x[63]
    DIRECTION INPUT ;
    USE SIGNAL ;
    PORT
      LAYER M4 ;
        RECT  0 78.912 0.084 78.936 ;
    END
  END x[63]
  PIN x[64]
    DIRECTION INPUT ;
    USE SIGNAL ;
    PORT
      LAYER M4 ;
        RECT  0 78.96 0.084 78.984 ;
    END
  END x[64]
  PIN x[65]
    DIRECTION INPUT ;
    USE SIGNAL ;
    PORT
      LAYER M4 ;
        RECT  0 79.008 0.084 79.032 ;
    END
  END x[65]
  PIN x[66]
    DIRECTION INPUT ;
    USE SIGNAL ;
    PORT
      LAYER M4 ;
        RECT  0 79.056 0.084 79.08 ;
    END
  END x[66]
  PIN x[67]
    DIRECTION INPUT ;
    USE SIGNAL ;
    PORT
      LAYER M4 ;
        RECT  0 79.104 0.084 79.128 ;
    END
  END x[67]
  PIN x[68]
    DIRECTION INPUT ;
    USE SIGNAL ;
    PORT
      LAYER M4 ;
        RECT  0 79.152 0.084 79.176 ;
    END
  END x[68]
  PIN x[69]
    DIRECTION INPUT ;
    USE SIGNAL ;
    PORT
      LAYER M4 ;
        RECT  0 79.2 0.084 79.224 ;
    END
  END x[69]
  PIN x[6]
    DIRECTION INPUT ;
    USE SIGNAL ;
    PORT
      LAYER M4 ;
        RECT  0 76.176 0.084 76.2 ;
    END
  END x[6]
  PIN x[70]
    DIRECTION INPUT ;
    USE SIGNAL ;
    PORT
      LAYER M4 ;
        RECT  0 79.248 0.084 79.272 ;
    END
  END x[70]
  PIN x[71]
    DIRECTION INPUT ;
    USE SIGNAL ;
    PORT
      LAYER M4 ;
        RECT  0 79.296 0.084 79.32 ;
    END
  END x[71]
  PIN x[72]
    DIRECTION INPUT ;
    USE SIGNAL ;
    PORT
      LAYER M4 ;
        RECT  0 79.344 0.084 79.368 ;
    END
  END x[72]
  PIN x[73]
    DIRECTION INPUT ;
    USE SIGNAL ;
    PORT
      LAYER M4 ;
        RECT  0 79.392 0.084 79.416 ;
    END
  END x[73]
  PIN x[74]
    DIRECTION INPUT ;
    USE SIGNAL ;
    PORT
      LAYER M4 ;
        RECT  0 79.44 0.084 79.464 ;
    END
  END x[74]
  PIN x[75]
    DIRECTION INPUT ;
    USE SIGNAL ;
    PORT
      LAYER M4 ;
        RECT  0 79.488 0.084 79.512 ;
    END
  END x[75]
  PIN x[76]
    DIRECTION INPUT ;
    USE SIGNAL ;
    PORT
      LAYER M4 ;
        RECT  0 79.536 0.084 79.56 ;
    END
  END x[76]
  PIN x[77]
    DIRECTION INPUT ;
    USE SIGNAL ;
    PORT
      LAYER M4 ;
        RECT  0 79.584 0.084 79.608 ;
    END
  END x[77]
  PIN x[78]
    DIRECTION INPUT ;
    USE SIGNAL ;
    PORT
      LAYER M4 ;
        RECT  0 79.632 0.084 79.656 ;
    END
  END x[78]
  PIN x[79]
    DIRECTION INPUT ;
    USE SIGNAL ;
    PORT
      LAYER M4 ;
        RECT  0 79.68 0.084 79.704 ;
    END
  END x[79]
  PIN x[7]
    DIRECTION INPUT ;
    USE SIGNAL ;
    PORT
      LAYER M4 ;
        RECT  0 76.224 0.084 76.248 ;
    END
  END x[7]
  PIN x[80]
    DIRECTION INPUT ;
    USE SIGNAL ;
    PORT
      LAYER M4 ;
        RECT  0 79.728 0.084 79.752 ;
    END
  END x[80]
  PIN x[81]
    DIRECTION INPUT ;
    USE SIGNAL ;
    PORT
      LAYER M4 ;
        RECT  0 79.776 0.084 79.8 ;
    END
  END x[81]
  PIN x[82]
    DIRECTION INPUT ;
    USE SIGNAL ;
    PORT
      LAYER M4 ;
        RECT  0 79.824 0.084 79.848 ;
    END
  END x[82]
  PIN x[83]
    DIRECTION INPUT ;
    USE SIGNAL ;
    PORT
      LAYER M4 ;
        RECT  0 79.872 0.084 79.896 ;
    END
  END x[83]
  PIN x[84]
    DIRECTION INPUT ;
    USE SIGNAL ;
    PORT
      LAYER M4 ;
        RECT  0 79.92 0.084 79.944 ;
    END
  END x[84]
  PIN x[85]
    DIRECTION INPUT ;
    USE SIGNAL ;
    PORT
      LAYER M4 ;
        RECT  0 79.968 0.084 79.992 ;
    END
  END x[85]
  PIN x[86]
    DIRECTION INPUT ;
    USE SIGNAL ;
    PORT
      LAYER M4 ;
        RECT  0 80.016 0.084 80.04 ;
    END
  END x[86]
  PIN x[87]
    DIRECTION INPUT ;
    USE SIGNAL ;
    PORT
      LAYER M4 ;
        RECT  0 80.064 0.084 80.088 ;
    END
  END x[87]
  PIN x[88]
    DIRECTION INPUT ;
    USE SIGNAL ;
    PORT
      LAYER M4 ;
        RECT  0 80.112 0.084 80.136 ;
    END
  END x[88]
  PIN x[89]
    DIRECTION INPUT ;
    USE SIGNAL ;
    PORT
      LAYER M4 ;
        RECT  0 80.16 0.084 80.184 ;
    END
  END x[89]
  PIN x[8]
    DIRECTION INPUT ;
    USE SIGNAL ;
    PORT
      LAYER M4 ;
        RECT  0 76.272 0.084 76.296 ;
    END
  END x[8]
  PIN x[90]
    DIRECTION INPUT ;
    USE SIGNAL ;
    PORT
      LAYER M4 ;
        RECT  0 80.208 0.084 80.232 ;
    END
  END x[90]
  PIN x[91]
    DIRECTION INPUT ;
    USE SIGNAL ;
    PORT
      LAYER M4 ;
        RECT  0 80.256 0.084 80.28 ;
    END
  END x[91]
  PIN x[92]
    DIRECTION INPUT ;
    USE SIGNAL ;
    PORT
      LAYER M4 ;
        RECT  0 80.304 0.084 80.328 ;
    END
  END x[92]
  PIN x[93]
    DIRECTION INPUT ;
    USE SIGNAL ;
    PORT
      LAYER M4 ;
        RECT  0 80.352 0.084 80.376 ;
    END
  END x[93]
  PIN x[94]
    DIRECTION INPUT ;
    USE SIGNAL ;
    PORT
      LAYER M4 ;
        RECT  0 80.4 0.084 80.424 ;
    END
  END x[94]
  PIN x[95]
    DIRECTION INPUT ;
    USE SIGNAL ;
    PORT
      LAYER M4 ;
        RECT  0 80.448 0.084 80.472 ;
    END
  END x[95]
  PIN x[96]
    DIRECTION INPUT ;
    USE SIGNAL ;
    PORT
      LAYER M4 ;
        RECT  0 80.496 0.084 80.52 ;
    END
  END x[96]
  PIN x[97]
    DIRECTION INPUT ;
    USE SIGNAL ;
    PORT
      LAYER M4 ;
        RECT  0 80.544 0.084 80.568 ;
    END
  END x[97]
  PIN x[98]
    DIRECTION INPUT ;
    USE SIGNAL ;
    PORT
      LAYER M4 ;
        RECT  0 80.592 0.084 80.616 ;
    END
  END x[98]
  PIN x[99]
    DIRECTION INPUT ;
    USE SIGNAL ;
    PORT
      LAYER M4 ;
        RECT  0 80.64 0.084 80.664 ;
    END
  END x[99]
  PIN x[9]
    DIRECTION INPUT ;
    USE SIGNAL ;
    PORT
      LAYER M4 ;
        RECT  0 76.32 0.084 76.344 ;
    END
  END x[9]
  PIN y[0]
    DIRECTION OUTPUT ;
    USE SIGNAL ;
    PORT
      LAYER M4 ;
        RECT  163.916 85.584 164 85.608 ;
    END
  END y[0]
  PIN y[10]
    DIRECTION OUTPUT ;
    USE SIGNAL ;
    PORT
      LAYER M4 ;
        RECT  163.916 86.064 164 86.088 ;
    END
  END y[10]
  PIN y[11]
    DIRECTION OUTPUT ;
    USE SIGNAL ;
    PORT
      LAYER M4 ;
        RECT  163.916 86.112 164 86.136 ;
    END
  END y[11]
  PIN y[12]
    DIRECTION OUTPUT ;
    USE SIGNAL ;
    PORT
      LAYER M4 ;
        RECT  163.916 86.16 164 86.184 ;
    END
  END y[12]
  PIN y[13]
    DIRECTION OUTPUT ;
    USE SIGNAL ;
    PORT
      LAYER M4 ;
        RECT  163.916 86.208 164 86.232 ;
    END
  END y[13]
  PIN y[14]
    DIRECTION OUTPUT ;
    USE SIGNAL ;
    PORT
      LAYER M4 ;
        RECT  163.916 86.256 164 86.28 ;
    END
  END y[14]
  PIN y[15]
    DIRECTION OUTPUT ;
    USE SIGNAL ;
    PORT
      LAYER M4 ;
        RECT  163.916 86.304 164 86.328 ;
    END
  END y[15]
  PIN y[16]
    DIRECTION OUTPUT ;
    USE SIGNAL ;
    PORT
      LAYER M4 ;
        RECT  163.916 86.352 164 86.376 ;
    END
  END y[16]
  PIN y[17]
    DIRECTION OUTPUT ;
    USE SIGNAL ;
    PORT
      LAYER M4 ;
        RECT  163.916 86.4 164 86.424 ;
    END
  END y[17]
  PIN y[18]
    DIRECTION OUTPUT ;
    USE SIGNAL ;
    PORT
      LAYER M4 ;
        RECT  163.916 86.448 164 86.472 ;
    END
  END y[18]
  PIN y[19]
    DIRECTION OUTPUT ;
    USE SIGNAL ;
    PORT
      LAYER M4 ;
        RECT  163.916 86.496 164 86.52 ;
    END
  END y[19]
  PIN y[1]
    DIRECTION OUTPUT ;
    USE SIGNAL ;
    PORT
      LAYER M4 ;
        RECT  163.916 85.632 164 85.656 ;
    END
  END y[1]
  PIN y[20]
    DIRECTION OUTPUT ;
    USE SIGNAL ;
    PORT
      LAYER M4 ;
        RECT  163.916 86.544 164 86.568 ;
    END
  END y[20]
  PIN y[21]
    DIRECTION OUTPUT ;
    USE SIGNAL ;
    PORT
      LAYER M4 ;
        RECT  163.916 86.592 164 86.616 ;
    END
  END y[21]
  PIN y[22]
    DIRECTION OUTPUT ;
    USE SIGNAL ;
    PORT
      LAYER M4 ;
        RECT  163.916 86.64 164 86.664 ;
    END
  END y[22]
  PIN y[23]
    DIRECTION OUTPUT ;
    USE SIGNAL ;
    PORT
      LAYER M4 ;
        RECT  163.916 86.688 164 86.712 ;
    END
  END y[23]
  PIN y[24]
    DIRECTION OUTPUT ;
    USE SIGNAL ;
    PORT
      LAYER M4 ;
        RECT  163.916 86.736 164 86.76 ;
    END
  END y[24]
  PIN y[25]
    DIRECTION OUTPUT ;
    USE SIGNAL ;
    PORT
      LAYER M4 ;
        RECT  163.916 86.784 164 86.808 ;
    END
  END y[25]
  PIN y[26]
    DIRECTION OUTPUT ;
    USE SIGNAL ;
    PORT
      LAYER M4 ;
        RECT  163.916 86.832 164 86.856 ;
    END
  END y[26]
  PIN y[27]
    DIRECTION OUTPUT ;
    USE SIGNAL ;
    PORT
      LAYER M4 ;
        RECT  163.916 86.88 164 86.904 ;
    END
  END y[27]
  PIN y[28]
    DIRECTION OUTPUT ;
    USE SIGNAL ;
    PORT
      LAYER M4 ;
        RECT  163.916 86.928 164 86.952 ;
    END
  END y[28]
  PIN y[29]
    DIRECTION OUTPUT ;
    USE SIGNAL ;
    PORT
      LAYER M4 ;
        RECT  163.916 86.976 164 87 ;
    END
  END y[29]
  PIN y[2]
    DIRECTION OUTPUT ;
    USE SIGNAL ;
    PORT
      LAYER M4 ;
        RECT  163.916 85.68 164 85.704 ;
    END
  END y[2]
  PIN y[30]
    DIRECTION OUTPUT ;
    USE SIGNAL ;
    PORT
      LAYER M4 ;
        RECT  163.916 87.024 164 87.048 ;
    END
  END y[30]
  PIN y[31]
    DIRECTION OUTPUT ;
    USE SIGNAL ;
    PORT
      LAYER M4 ;
        RECT  163.916 87.072 164 87.096 ;
    END
  END y[31]
  PIN y[3]
    DIRECTION OUTPUT ;
    USE SIGNAL ;
    PORT
      LAYER M4 ;
        RECT  163.916 85.728 164 85.752 ;
    END
  END y[3]
  PIN y[4]
    DIRECTION OUTPUT ;
    USE SIGNAL ;
    PORT
      LAYER M4 ;
        RECT  163.916 85.776 164 85.8 ;
    END
  END y[4]
  PIN y[5]
    DIRECTION OUTPUT ;
    USE SIGNAL ;
    PORT
      LAYER M4 ;
        RECT  163.916 85.824 164 85.848 ;
    END
  END y[5]
  PIN y[6]
    DIRECTION OUTPUT ;
    USE SIGNAL ;
    PORT
      LAYER M4 ;
        RECT  163.916 85.872 164 85.896 ;
    END
  END y[6]
  PIN y[7]
    DIRECTION OUTPUT ;
    USE SIGNAL ;
    PORT
      LAYER M4 ;
        RECT  163.916 85.92 164 85.944 ;
    END
  END y[7]
  PIN y[8]
    DIRECTION OUTPUT ;
    USE SIGNAL ;
    PORT
      LAYER M4 ;
        RECT  163.916 85.968 164 85.992 ;
    END
  END y[8]
  PIN y[9]
    DIRECTION OUTPUT ;
    USE SIGNAL ;
    PORT
      LAYER M4 ;
        RECT  163.916 86.016 164 86.04 ;
    END
  END y[9]
  PIN VDD
    DIRECTION INOUT ;
    USE POWER ;
    PORT
      LAYER M6 ;
        RECT  1.44 155.6 162.612 155.888 ;
        RECT  1.44 144.8 162.612 145.088 ;
        RECT  1.44 134 162.612 134.288 ;
        RECT  1.44 123.2 162.612 123.488 ;
        RECT  1.44 112.4 162.612 112.688 ;
        RECT  1.44 101.6 162.612 101.888 ;
        RECT  1.44 90.8 162.612 91.088 ;
        RECT  1.44 80 162.612 80.288 ;
        RECT  1.44 69.2 162.612 69.488 ;
        RECT  1.44 58.4 162.612 58.688 ;
        RECT  1.44 47.6 162.612 47.888 ;
        RECT  1.44 36.8 162.612 37.088 ;
        RECT  1.44 26 162.612 26.288 ;
        RECT  1.44 15.2 162.612 15.488 ;
        RECT  1.44 4.4 162.612 4.688 ;
        RECT  1.44 162.684 162.612 162.972 ;
        RECT  1.44 1.188 162.612 1.476 ;
    END
  END VDD
  PIN VSS
    DIRECTION INOUT ;
    USE GROUND ;
    PORT
      LAYER M6 ;
        RECT  1.44 155.216 162.612 155.504 ;
        RECT  1.44 144.416 162.612 144.704 ;
        RECT  1.44 133.616 162.612 133.904 ;
        RECT  1.44 122.816 162.612 123.104 ;
        RECT  1.44 112.016 162.612 112.304 ;
        RECT  1.44 101.216 162.612 101.504 ;
        RECT  1.44 90.416 162.612 90.704 ;
        RECT  1.44 79.616 162.612 79.904 ;
        RECT  1.44 68.816 162.612 69.104 ;
        RECT  1.44 58.016 162.612 58.304 ;
        RECT  1.44 47.216 162.612 47.504 ;
        RECT  1.44 36.416 162.612 36.704 ;
        RECT  1.44 25.616 162.612 25.904 ;
        RECT  1.44 14.816 162.612 15.104 ;
        RECT  1.44 4.016 162.612 4.304 ;
        RECT  1.632 162.3 162.42 162.588 ;
        RECT  1.632 1.572 162.42 1.86 ;
    END
  END VSS
  OBS
    LAYER RVTN ;
     RECT  0 0 164 164 ;
    LAYER RVTP ;
     RECT  0 0 164 164 ;
    LAYER M1 ;
     RECT  0 0 164 164 ;
    LAYER M2 ;
     RECT  0 0 164 164 ;
    LAYER M3 ;
     RECT  0 0 164 164 ;
    LAYER M4 ;
     RECT  0 0 164 164 ;
    LAYER M5 ;
     RECT  0 0 164 164 ;
    LAYER M6 ;
     RECT  0 0 164 164 ;
  END
END ot_gpu_tc16
END LIBRARY
